VERSION 5.7 ;
  NOWIREEXTENSIONATPIN ON ;
  DIVIDERCHAR "/" ;
  BUSBITCHARS "[]" ;
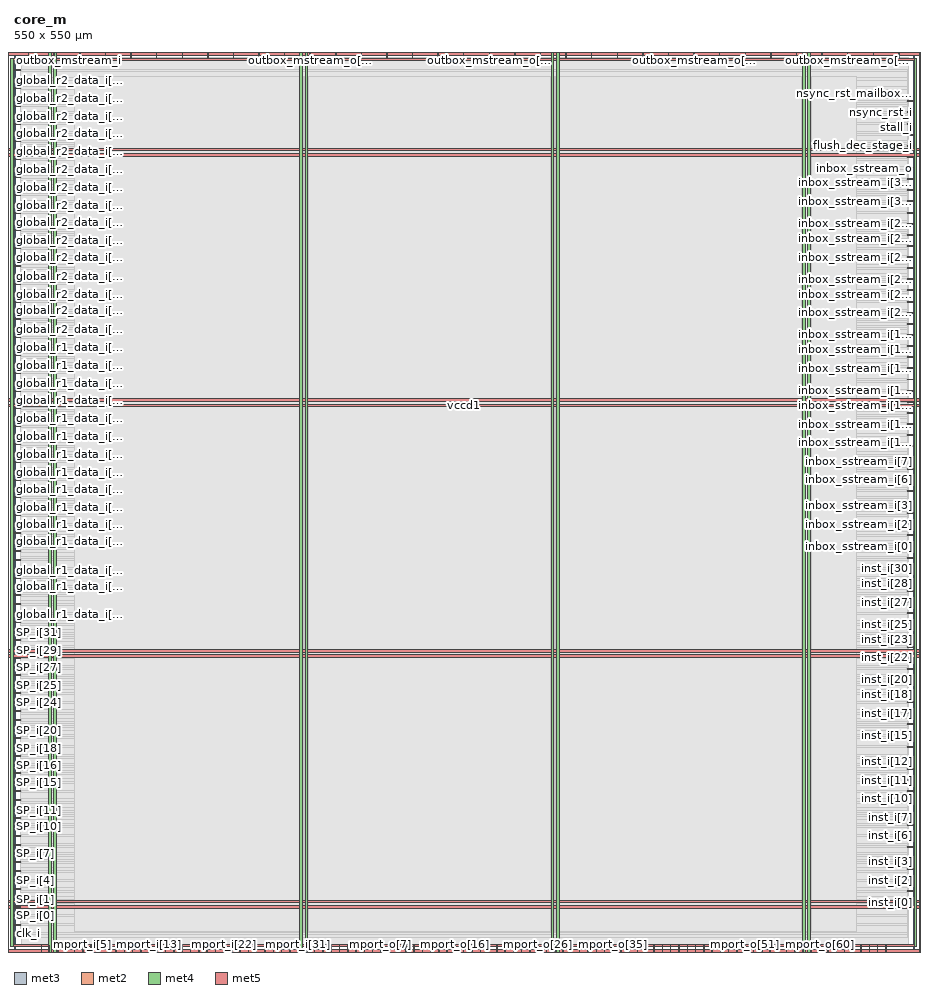
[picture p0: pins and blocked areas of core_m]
MACRO core_m
  CLASS BLOCK ;
  FOREIGN core_m ;
  ORIGIN 0.000 0.000 ;
  SIZE 550.000 BY 550.000 ;
  PIN SP_i[0]
    DIRECTION INPUT ;
    USE SIGNAL ;
    ANTENNAGATEAREA 0.159000 ;
    PORT
      LAYER met3 ;
        RECT 0.000 21.800 4.000 22.400 ;
    END
  END SP_i[0]
  PIN SP_i[10]
    DIRECTION INPUT ;
    USE SIGNAL ;
    ANTENNAGATEAREA 0.213000 ;
    PORT
      LAYER met3 ;
        RECT 0.000 76.200 4.000 76.800 ;
    END
  END SP_i[10]
  PIN SP_i[11]
    DIRECTION INPUT ;
    USE SIGNAL ;
    ANTENNAGATEAREA 0.213000 ;
    PORT
      LAYER met3 ;
        RECT 0.000 81.640 4.000 82.240 ;
    END
  END SP_i[11]
  PIN SP_i[12]
    DIRECTION INPUT ;
    USE SIGNAL ;
    ANTENNAGATEAREA 0.213000 ;
    PORT
      LAYER met3 ;
        RECT 0.000 87.080 4.000 87.680 ;
    END
  END SP_i[12]
  PIN SP_i[13]
    DIRECTION INPUT ;
    USE SIGNAL ;
    ANTENNAGATEAREA 0.213000 ;
    PORT
      LAYER met3 ;
        RECT 0.000 92.520 4.000 93.120 ;
    END
  END SP_i[13]
  PIN SP_i[14]
    DIRECTION INPUT ;
    USE SIGNAL ;
    ANTENNAGATEAREA 0.213000 ;
    PORT
      LAYER met3 ;
        RECT 0.000 97.960 4.000 98.560 ;
    END
  END SP_i[14]
  PIN SP_i[15]
    DIRECTION INPUT ;
    USE SIGNAL ;
    ANTENNAGATEAREA 0.213000 ;
    PORT
      LAYER met3 ;
        RECT 0.000 103.400 4.000 104.000 ;
    END
  END SP_i[15]
  PIN SP_i[16]
    DIRECTION INPUT ;
    USE SIGNAL ;
    ANTENNAGATEAREA 0.213000 ;
    PORT
      LAYER met3 ;
        RECT 0.000 108.840 4.000 109.440 ;
    END
  END SP_i[16]
  PIN SP_i[17]
    DIRECTION INPUT ;
    USE SIGNAL ;
    ANTENNAGATEAREA 0.213000 ;
    PORT
      LAYER met3 ;
        RECT 0.000 114.280 4.000 114.880 ;
    END
  END SP_i[17]
  PIN SP_i[18]
    DIRECTION INPUT ;
    USE SIGNAL ;
    ANTENNAGATEAREA 0.213000 ;
    PORT
      LAYER met3 ;
        RECT 0.000 119.720 4.000 120.320 ;
    END
  END SP_i[18]
  PIN SP_i[19]
    DIRECTION INPUT ;
    USE SIGNAL ;
    ANTENNAGATEAREA 0.213000 ;
    PORT
      LAYER met3 ;
        RECT 0.000 125.160 4.000 125.760 ;
    END
  END SP_i[19]
  PIN SP_i[1]
    DIRECTION INPUT ;
    USE SIGNAL ;
    ANTENNAGATEAREA 0.213000 ;
    PORT
      LAYER met3 ;
        RECT 0.000 27.240 4.000 27.840 ;
    END
  END SP_i[1]
  PIN SP_i[20]
    DIRECTION INPUT ;
    USE SIGNAL ;
    ANTENNAGATEAREA 0.213000 ;
    PORT
      LAYER met3 ;
        RECT 0.000 130.600 4.000 131.200 ;
    END
  END SP_i[20]
  PIN SP_i[21]
    DIRECTION INPUT ;
    USE SIGNAL ;
    ANTENNAGATEAREA 0.213000 ;
    PORT
      LAYER met3 ;
        RECT 0.000 136.040 4.000 136.640 ;
    END
  END SP_i[21]
  PIN SP_i[22]
    DIRECTION INPUT ;
    USE SIGNAL ;
    ANTENNAGATEAREA 0.213000 ;
    PORT
      LAYER met3 ;
        RECT 0.000 141.480 4.000 142.080 ;
    END
  END SP_i[22]
  PIN SP_i[23]
    DIRECTION INPUT ;
    USE SIGNAL ;
    ANTENNAGATEAREA 0.247500 ;
    PORT
      LAYER met3 ;
        RECT 0.000 146.920 4.000 147.520 ;
    END
  END SP_i[23]
  PIN SP_i[24]
    DIRECTION INPUT ;
    USE SIGNAL ;
    ANTENNAGATEAREA 0.159000 ;
    PORT
      LAYER met3 ;
        RECT 0.000 152.360 4.000 152.960 ;
    END
  END SP_i[24]
  PIN SP_i[25]
    DIRECTION INPUT ;
    USE SIGNAL ;
    ANTENNAGATEAREA 0.247500 ;
    PORT
      LAYER met3 ;
        RECT 0.000 157.800 4.000 158.400 ;
    END
  END SP_i[25]
  PIN SP_i[26]
    DIRECTION INPUT ;
    USE SIGNAL ;
    ANTENNAGATEAREA 0.213000 ;
    PORT
      LAYER met3 ;
        RECT 0.000 163.240 4.000 163.840 ;
    END
  END SP_i[26]
  PIN SP_i[27]
    DIRECTION INPUT ;
    USE SIGNAL ;
    ANTENNAGATEAREA 0.247500 ;
    PORT
      LAYER met3 ;
        RECT 0.000 168.680 4.000 169.280 ;
    END
  END SP_i[27]
  PIN SP_i[28]
    DIRECTION INPUT ;
    USE SIGNAL ;
    ANTENNAGATEAREA 0.247500 ;
    PORT
      LAYER met3 ;
        RECT 0.000 174.120 4.000 174.720 ;
    END
  END SP_i[28]
  PIN SP_i[29]
    DIRECTION INPUT ;
    USE SIGNAL ;
    ANTENNAGATEAREA 0.247500 ;
    PORT
      LAYER met3 ;
        RECT 0.000 179.560 4.000 180.160 ;
    END
  END SP_i[29]
  PIN SP_i[2]
    DIRECTION INPUT ;
    USE SIGNAL ;
    ANTENNAGATEAREA 0.213000 ;
    PORT
      LAYER met3 ;
        RECT 0.000 32.680 4.000 33.280 ;
    END
  END SP_i[2]
  PIN SP_i[30]
    DIRECTION INPUT ;
    USE SIGNAL ;
    ANTENNAGATEAREA 0.247500 ;
    PORT
      LAYER met3 ;
        RECT 0.000 185.000 4.000 185.600 ;
    END
  END SP_i[30]
  PIN SP_i[31]
    DIRECTION INPUT ;
    USE SIGNAL ;
    ANTENNAGATEAREA 0.213000 ;
    PORT
      LAYER met3 ;
        RECT 0.000 190.440 4.000 191.040 ;
    END
  END SP_i[31]
  PIN SP_i[3]
    DIRECTION INPUT ;
    USE SIGNAL ;
    ANTENNAGATEAREA 0.159000 ;
    PORT
      LAYER met3 ;
        RECT 0.000 38.120 4.000 38.720 ;
    END
  END SP_i[3]
  PIN SP_i[4]
    DIRECTION INPUT ;
    USE SIGNAL ;
    ANTENNAGATEAREA 0.213000 ;
    PORT
      LAYER met3 ;
        RECT 0.000 43.560 4.000 44.160 ;
    END
  END SP_i[4]
  PIN SP_i[5]
    DIRECTION INPUT ;
    USE SIGNAL ;
    ANTENNAGATEAREA 0.213000 ;
    PORT
      LAYER met3 ;
        RECT 0.000 49.000 4.000 49.600 ;
    END
  END SP_i[5]
  PIN SP_i[6]
    DIRECTION INPUT ;
    USE SIGNAL ;
    ANTENNAGATEAREA 0.213000 ;
    PORT
      LAYER met3 ;
        RECT 0.000 54.440 4.000 55.040 ;
    END
  END SP_i[6]
  PIN SP_i[7]
    DIRECTION INPUT ;
    USE SIGNAL ;
    ANTENNAGATEAREA 0.213000 ;
    PORT
      LAYER met3 ;
        RECT 0.000 59.880 4.000 60.480 ;
    END
  END SP_i[7]
  PIN SP_i[8]
    DIRECTION INPUT ;
    USE SIGNAL ;
    ANTENNAGATEAREA 0.213000 ;
    PORT
      LAYER met3 ;
        RECT 0.000 65.320 4.000 65.920 ;
    END
  END SP_i[8]
  PIN SP_i[9]
    DIRECTION INPUT ;
    USE SIGNAL ;
    ANTENNAGATEAREA 0.213000 ;
    PORT
      LAYER met3 ;
        RECT 0.000 70.760 4.000 71.360 ;
    END
  END SP_i[9]
  PIN clk_i
    DIRECTION INPUT ;
    USE SIGNAL ;
    ANTENNAGATEAREA 0.852000 ;
    PORT
      LAYER met3 ;
        RECT 0.000 10.920 4.000 11.520 ;
    END
  END clk_i
  PIN flush_dec_stage_i
    DIRECTION INPUT ;
    USE SIGNAL ;
    ANTENNAGATEAREA 0.247500 ;
    PORT
      LAYER met3 ;
        RECT 546.000 492.360 550.000 492.960 ;
    END
  END flush_dec_stage_i
  PIN global_r1_data_i[0]
    DIRECTION INPUT ;
    USE SIGNAL ;
    ANTENNAGATEAREA 0.196500 ;
    PORT
      LAYER met3 ;
        RECT 0.000 195.880 4.000 196.480 ;
    END
  END global_r1_data_i[0]
  PIN global_r1_data_i[10]
    DIRECTION INPUT ;
    USE SIGNAL ;
    ANTENNAGATEAREA 0.196500 ;
    PORT
      LAYER met3 ;
        RECT 0.000 250.280 4.000 250.880 ;
    END
  END global_r1_data_i[10]
  PIN global_r1_data_i[11]
    DIRECTION INPUT ;
    USE SIGNAL ;
    ANTENNAGATEAREA 0.196500 ;
    PORT
      LAYER met3 ;
        RECT 0.000 255.720 4.000 256.320 ;
    END
  END global_r1_data_i[11]
  PIN global_r1_data_i[12]
    DIRECTION INPUT ;
    USE SIGNAL ;
    ANTENNAGATEAREA 0.196500 ;
    PORT
      LAYER met3 ;
        RECT 0.000 261.160 4.000 261.760 ;
    END
  END global_r1_data_i[12]
  PIN global_r1_data_i[13]
    DIRECTION INPUT ;
    USE SIGNAL ;
    ANTENNAGATEAREA 0.196500 ;
    PORT
      LAYER met3 ;
        RECT 0.000 266.600 4.000 267.200 ;
    END
  END global_r1_data_i[13]
  PIN global_r1_data_i[14]
    DIRECTION INPUT ;
    USE SIGNAL ;
    ANTENNAGATEAREA 0.196500 ;
    PORT
      LAYER met3 ;
        RECT 0.000 272.040 4.000 272.640 ;
    END
  END global_r1_data_i[14]
  PIN global_r1_data_i[15]
    DIRECTION INPUT ;
    USE SIGNAL ;
    ANTENNAGATEAREA 0.196500 ;
    PORT
      LAYER met3 ;
        RECT 0.000 277.480 4.000 278.080 ;
    END
  END global_r1_data_i[15]
  PIN global_r1_data_i[16]
    DIRECTION INPUT ;
    USE SIGNAL ;
    ANTENNAGATEAREA 0.196500 ;
    PORT
      LAYER met3 ;
        RECT 0.000 282.920 4.000 283.520 ;
    END
  END global_r1_data_i[16]
  PIN global_r1_data_i[17]
    DIRECTION INPUT ;
    USE SIGNAL ;
    ANTENNAGATEAREA 0.196500 ;
    PORT
      LAYER met3 ;
        RECT 0.000 288.360 4.000 288.960 ;
    END
  END global_r1_data_i[17]
  PIN global_r1_data_i[18]
    DIRECTION INPUT ;
    USE SIGNAL ;
    ANTENNAGATEAREA 0.196500 ;
    PORT
      LAYER met3 ;
        RECT 0.000 293.800 4.000 294.400 ;
    END
  END global_r1_data_i[18]
  PIN global_r1_data_i[19]
    DIRECTION INPUT ;
    USE SIGNAL ;
    ANTENNAGATEAREA 0.196500 ;
    PORT
      LAYER met3 ;
        RECT 0.000 299.240 4.000 299.840 ;
    END
  END global_r1_data_i[19]
  PIN global_r1_data_i[1]
    DIRECTION INPUT ;
    USE SIGNAL ;
    ANTENNAGATEAREA 0.196500 ;
    PORT
      LAYER met3 ;
        RECT 0.000 201.320 4.000 201.920 ;
    END
  END global_r1_data_i[1]
  PIN global_r1_data_i[20]
    DIRECTION INPUT ;
    USE SIGNAL ;
    ANTENNAGATEAREA 0.196500 ;
    PORT
      LAYER met3 ;
        RECT 0.000 304.680 4.000 305.280 ;
    END
  END global_r1_data_i[20]
  PIN global_r1_data_i[21]
    DIRECTION INPUT ;
    USE SIGNAL ;
    ANTENNAGATEAREA 0.196500 ;
    PORT
      LAYER met3 ;
        RECT 0.000 310.120 4.000 310.720 ;
    END
  END global_r1_data_i[21]
  PIN global_r1_data_i[22]
    DIRECTION INPUT ;
    USE SIGNAL ;
    ANTENNAGATEAREA 0.196500 ;
    PORT
      LAYER met3 ;
        RECT 0.000 315.560 4.000 316.160 ;
    END
  END global_r1_data_i[22]
  PIN global_r1_data_i[23]
    DIRECTION INPUT ;
    USE SIGNAL ;
    ANTENNAGATEAREA 0.196500 ;
    PORT
      LAYER met3 ;
        RECT 0.000 321.000 4.000 321.600 ;
    END
  END global_r1_data_i[23]
  PIN global_r1_data_i[24]
    DIRECTION INPUT ;
    USE SIGNAL ;
    ANTENNAGATEAREA 0.196500 ;
    PORT
      LAYER met3 ;
        RECT 0.000 326.440 4.000 327.040 ;
    END
  END global_r1_data_i[24]
  PIN global_r1_data_i[25]
    DIRECTION INPUT ;
    USE SIGNAL ;
    ANTENNAGATEAREA 0.196500 ;
    PORT
      LAYER met3 ;
        RECT 0.000 331.880 4.000 332.480 ;
    END
  END global_r1_data_i[25]
  PIN global_r1_data_i[26]
    DIRECTION INPUT ;
    USE SIGNAL ;
    ANTENNAGATEAREA 0.196500 ;
    PORT
      LAYER met3 ;
        RECT 0.000 337.320 4.000 337.920 ;
    END
  END global_r1_data_i[26]
  PIN global_r1_data_i[27]
    DIRECTION INPUT ;
    USE SIGNAL ;
    ANTENNAGATEAREA 0.196500 ;
    PORT
      LAYER met3 ;
        RECT 0.000 342.760 4.000 343.360 ;
    END
  END global_r1_data_i[27]
  PIN global_r1_data_i[28]
    DIRECTION INPUT ;
    USE SIGNAL ;
    ANTENNAGATEAREA 0.196500 ;
    PORT
      LAYER met3 ;
        RECT 0.000 348.200 4.000 348.800 ;
    END
  END global_r1_data_i[28]
  PIN global_r1_data_i[29]
    DIRECTION INPUT ;
    USE SIGNAL ;
    ANTENNAGATEAREA 0.196500 ;
    PORT
      LAYER met3 ;
        RECT 0.000 353.640 4.000 354.240 ;
    END
  END global_r1_data_i[29]
  PIN global_r1_data_i[2]
    DIRECTION INPUT ;
    USE SIGNAL ;
    ANTENNAGATEAREA 0.196500 ;
    PORT
      LAYER met3 ;
        RECT 0.000 206.760 4.000 207.360 ;
    END
  END global_r1_data_i[2]
  PIN global_r1_data_i[30]
    DIRECTION INPUT ;
    USE SIGNAL ;
    ANTENNAGATEAREA 0.196500 ;
    PORT
      LAYER met3 ;
        RECT 0.000 359.080 4.000 359.680 ;
    END
  END global_r1_data_i[30]
  PIN global_r1_data_i[31]
    DIRECTION INPUT ;
    USE SIGNAL ;
    ANTENNAGATEAREA 0.196500 ;
    PORT
      LAYER met3 ;
        RECT 0.000 364.520 4.000 365.120 ;
    END
  END global_r1_data_i[31]
  PIN global_r1_data_i[3]
    DIRECTION INPUT ;
    USE SIGNAL ;
    ANTENNAGATEAREA 0.196500 ;
    PORT
      LAYER met3 ;
        RECT 0.000 212.200 4.000 212.800 ;
    END
  END global_r1_data_i[3]
  PIN global_r1_data_i[4]
    DIRECTION INPUT ;
    USE SIGNAL ;
    ANTENNAGATEAREA 0.196500 ;
    PORT
      LAYER met3 ;
        RECT 0.000 217.640 4.000 218.240 ;
    END
  END global_r1_data_i[4]
  PIN global_r1_data_i[5]
    DIRECTION INPUT ;
    USE SIGNAL ;
    ANTENNAGATEAREA 0.196500 ;
    PORT
      LAYER met3 ;
        RECT 0.000 223.080 4.000 223.680 ;
    END
  END global_r1_data_i[5]
  PIN global_r1_data_i[6]
    DIRECTION INPUT ;
    USE SIGNAL ;
    ANTENNAGATEAREA 0.196500 ;
    PORT
      LAYER met3 ;
        RECT 0.000 228.520 4.000 229.120 ;
    END
  END global_r1_data_i[6]
  PIN global_r1_data_i[7]
    DIRECTION INPUT ;
    USE SIGNAL ;
    ANTENNAGATEAREA 0.196500 ;
    PORT
      LAYER met3 ;
        RECT 0.000 233.960 4.000 234.560 ;
    END
  END global_r1_data_i[7]
  PIN global_r1_data_i[8]
    DIRECTION INPUT ;
    USE SIGNAL ;
    ANTENNAGATEAREA 0.196500 ;
    PORT
      LAYER met3 ;
        RECT 0.000 239.400 4.000 240.000 ;
    END
  END global_r1_data_i[8]
  PIN global_r1_data_i[9]
    DIRECTION INPUT ;
    USE SIGNAL ;
    ANTENNAGATEAREA 0.196500 ;
    PORT
      LAYER met3 ;
        RECT 0.000 244.840 4.000 245.440 ;
    END
  END global_r1_data_i[9]
  PIN global_r2_data_i[0]
    DIRECTION INPUT ;
    USE SIGNAL ;
    ANTENNAGATEAREA 0.196500 ;
    PORT
      LAYER met3 ;
        RECT 0.000 369.960 4.000 370.560 ;
    END
  END global_r2_data_i[0]
  PIN global_r2_data_i[10]
    DIRECTION INPUT ;
    USE SIGNAL ;
    ANTENNAGATEAREA 0.196500 ;
    PORT
      LAYER met3 ;
        RECT 0.000 424.360 4.000 424.960 ;
    END
  END global_r2_data_i[10]
  PIN global_r2_data_i[11]
    DIRECTION INPUT ;
    USE SIGNAL ;
    ANTENNAGATEAREA 0.196500 ;
    PORT
      LAYER met3 ;
        RECT 0.000 429.800 4.000 430.400 ;
    END
  END global_r2_data_i[11]
  PIN global_r2_data_i[12]
    DIRECTION INPUT ;
    USE SIGNAL ;
    ANTENNAGATEAREA 0.196500 ;
    PORT
      LAYER met3 ;
        RECT 0.000 435.240 4.000 435.840 ;
    END
  END global_r2_data_i[12]
  PIN global_r2_data_i[13]
    DIRECTION INPUT ;
    USE SIGNAL ;
    ANTENNAGATEAREA 0.196500 ;
    PORT
      LAYER met3 ;
        RECT 0.000 440.680 4.000 441.280 ;
    END
  END global_r2_data_i[13]
  PIN global_r2_data_i[14]
    DIRECTION INPUT ;
    USE SIGNAL ;
    ANTENNAGATEAREA 0.196500 ;
    PORT
      LAYER met3 ;
        RECT 0.000 446.120 4.000 446.720 ;
    END
  END global_r2_data_i[14]
  PIN global_r2_data_i[15]
    DIRECTION INPUT ;
    USE SIGNAL ;
    ANTENNAGATEAREA 0.196500 ;
    PORT
      LAYER met3 ;
        RECT 0.000 451.560 4.000 452.160 ;
    END
  END global_r2_data_i[15]
  PIN global_r2_data_i[16]
    DIRECTION INPUT ;
    USE SIGNAL ;
    ANTENNAGATEAREA 0.196500 ;
    PORT
      LAYER met3 ;
        RECT 0.000 457.000 4.000 457.600 ;
    END
  END global_r2_data_i[16]
  PIN global_r2_data_i[17]
    DIRECTION INPUT ;
    USE SIGNAL ;
    ANTENNAGATEAREA 0.196500 ;
    PORT
      LAYER met3 ;
        RECT 0.000 462.440 4.000 463.040 ;
    END
  END global_r2_data_i[17]
  PIN global_r2_data_i[18]
    DIRECTION INPUT ;
    USE SIGNAL ;
    ANTENNAGATEAREA 0.196500 ;
    PORT
      LAYER met3 ;
        RECT 0.000 467.880 4.000 468.480 ;
    END
  END global_r2_data_i[18]
  PIN global_r2_data_i[19]
    DIRECTION INPUT ;
    USE SIGNAL ;
    ANTENNAGATEAREA 0.196500 ;
    PORT
      LAYER met3 ;
        RECT 0.000 473.320 4.000 473.920 ;
    END
  END global_r2_data_i[19]
  PIN global_r2_data_i[1]
    DIRECTION INPUT ;
    USE SIGNAL ;
    ANTENNAGATEAREA 0.196500 ;
    PORT
      LAYER met3 ;
        RECT 0.000 375.400 4.000 376.000 ;
    END
  END global_r2_data_i[1]
  PIN global_r2_data_i[20]
    DIRECTION INPUT ;
    USE SIGNAL ;
    ANTENNAGATEAREA 0.196500 ;
    PORT
      LAYER met3 ;
        RECT 0.000 478.760 4.000 479.360 ;
    END
  END global_r2_data_i[20]
  PIN global_r2_data_i[21]
    DIRECTION INPUT ;
    USE SIGNAL ;
    ANTENNAGATEAREA 0.196500 ;
    PORT
      LAYER met3 ;
        RECT 0.000 484.200 4.000 484.800 ;
    END
  END global_r2_data_i[21]
  PIN global_r2_data_i[22]
    DIRECTION INPUT ;
    USE SIGNAL ;
    ANTENNAGATEAREA 0.196500 ;
    PORT
      LAYER met3 ;
        RECT 0.000 489.640 4.000 490.240 ;
    END
  END global_r2_data_i[22]
  PIN global_r2_data_i[23]
    DIRECTION INPUT ;
    USE SIGNAL ;
    ANTENNAGATEAREA 0.196500 ;
    PORT
      LAYER met3 ;
        RECT 0.000 495.080 4.000 495.680 ;
    END
  END global_r2_data_i[23]
  PIN global_r2_data_i[24]
    DIRECTION INPUT ;
    USE SIGNAL ;
    ANTENNAGATEAREA 0.196500 ;
    PORT
      LAYER met3 ;
        RECT 0.000 500.520 4.000 501.120 ;
    END
  END global_r2_data_i[24]
  PIN global_r2_data_i[25]
    DIRECTION INPUT ;
    USE SIGNAL ;
    ANTENNAGATEAREA 0.196500 ;
    PORT
      LAYER met3 ;
        RECT 0.000 505.960 4.000 506.560 ;
    END
  END global_r2_data_i[25]
  PIN global_r2_data_i[26]
    DIRECTION INPUT ;
    USE SIGNAL ;
    ANTENNAGATEAREA 0.196500 ;
    PORT
      LAYER met3 ;
        RECT 0.000 511.400 4.000 512.000 ;
    END
  END global_r2_data_i[26]
  PIN global_r2_data_i[27]
    DIRECTION INPUT ;
    USE SIGNAL ;
    ANTENNAGATEAREA 0.196500 ;
    PORT
      LAYER met3 ;
        RECT 0.000 516.840 4.000 517.440 ;
    END
  END global_r2_data_i[27]
  PIN global_r2_data_i[28]
    DIRECTION INPUT ;
    USE SIGNAL ;
    ANTENNAGATEAREA 0.196500 ;
    PORT
      LAYER met3 ;
        RECT 0.000 522.280 4.000 522.880 ;
    END
  END global_r2_data_i[28]
  PIN global_r2_data_i[29]
    DIRECTION INPUT ;
    USE SIGNAL ;
    ANTENNAGATEAREA 0.196500 ;
    PORT
      LAYER met3 ;
        RECT 0.000 527.720 4.000 528.320 ;
    END
  END global_r2_data_i[29]
  PIN global_r2_data_i[2]
    DIRECTION INPUT ;
    USE SIGNAL ;
    ANTENNAGATEAREA 0.196500 ;
    PORT
      LAYER met3 ;
        RECT 0.000 380.840 4.000 381.440 ;
    END
  END global_r2_data_i[2]
  PIN global_r2_data_i[30]
    DIRECTION INPUT ;
    USE SIGNAL ;
    ANTENNAGATEAREA 0.196500 ;
    PORT
      LAYER met3 ;
        RECT 0.000 533.160 4.000 533.760 ;
    END
  END global_r2_data_i[30]
  PIN global_r2_data_i[31]
    DIRECTION INPUT ;
    USE SIGNAL ;
    ANTENNAGATEAREA 0.196500 ;
    PORT
      LAYER met3 ;
        RECT 0.000 538.600 4.000 539.200 ;
    END
  END global_r2_data_i[31]
  PIN global_r2_data_i[3]
    DIRECTION INPUT ;
    USE SIGNAL ;
    ANTENNAGATEAREA 0.196500 ;
    PORT
      LAYER met3 ;
        RECT 0.000 386.280 4.000 386.880 ;
    END
  END global_r2_data_i[3]
  PIN global_r2_data_i[4]
    DIRECTION INPUT ;
    USE SIGNAL ;
    ANTENNAGATEAREA 0.196500 ;
    PORT
      LAYER met3 ;
        RECT 0.000 391.720 4.000 392.320 ;
    END
  END global_r2_data_i[4]
  PIN global_r2_data_i[5]
    DIRECTION INPUT ;
    USE SIGNAL ;
    ANTENNAGATEAREA 0.196500 ;
    PORT
      LAYER met3 ;
        RECT 0.000 397.160 4.000 397.760 ;
    END
  END global_r2_data_i[5]
  PIN global_r2_data_i[6]
    DIRECTION INPUT ;
    USE SIGNAL ;
    ANTENNAGATEAREA 0.196500 ;
    PORT
      LAYER met3 ;
        RECT 0.000 402.600 4.000 403.200 ;
    END
  END global_r2_data_i[6]
  PIN global_r2_data_i[7]
    DIRECTION INPUT ;
    USE SIGNAL ;
    ANTENNAGATEAREA 0.196500 ;
    PORT
      LAYER met3 ;
        RECT 0.000 408.040 4.000 408.640 ;
    END
  END global_r2_data_i[7]
  PIN global_r2_data_i[8]
    DIRECTION INPUT ;
    USE SIGNAL ;
    ANTENNAGATEAREA 0.196500 ;
    PORT
      LAYER met3 ;
        RECT 0.000 413.480 4.000 414.080 ;
    END
  END global_r2_data_i[8]
  PIN global_r2_data_i[9]
    DIRECTION INPUT ;
    USE SIGNAL ;
    ANTENNAGATEAREA 0.196500 ;
    PORT
      LAYER met3 ;
        RECT 0.000 418.920 4.000 419.520 ;
    END
  END global_r2_data_i[9]
  PIN inbox_sstream_i[0]
    DIRECTION INPUT ;
    USE SIGNAL ;
    ANTENNAGATEAREA 0.159000 ;
    PORT
      LAYER met3 ;
        RECT 546.000 247.560 550.000 248.160 ;
    END
  END inbox_sstream_i[0]
  PIN inbox_sstream_i[10]
    DIRECTION INPUT ;
    USE SIGNAL ;
    ANTENNAGATEAREA 0.159000 ;
    PORT
      LAYER met3 ;
        RECT 546.000 315.560 550.000 316.160 ;
    END
  END inbox_sstream_i[10]
  PIN inbox_sstream_i[11]
    DIRECTION INPUT ;
    USE SIGNAL ;
    ANTENNAGATEAREA 0.213000 ;
    PORT
      LAYER met3 ;
        RECT 546.000 322.360 550.000 322.960 ;
    END
  END inbox_sstream_i[11]
  PIN inbox_sstream_i[12]
    DIRECTION INPUT ;
    USE SIGNAL ;
    ANTENNAGATEAREA 0.213000 ;
    PORT
      LAYER met3 ;
        RECT 546.000 329.160 550.000 329.760 ;
    END
  END inbox_sstream_i[12]
  PIN inbox_sstream_i[13]
    DIRECTION INPUT ;
    USE SIGNAL ;
    ANTENNAGATEAREA 0.213000 ;
    PORT
      LAYER met3 ;
        RECT 546.000 335.960 550.000 336.560 ;
    END
  END inbox_sstream_i[13]
  PIN inbox_sstream_i[14]
    DIRECTION INPUT ;
    USE SIGNAL ;
    ANTENNAGATEAREA 0.159000 ;
    PORT
      LAYER met3 ;
        RECT 546.000 342.760 550.000 343.360 ;
    END
  END inbox_sstream_i[14]
  PIN inbox_sstream_i[15]
    DIRECTION INPUT ;
    USE SIGNAL ;
    ANTENNAGATEAREA 0.213000 ;
    PORT
      LAYER met3 ;
        RECT 546.000 349.560 550.000 350.160 ;
    END
  END inbox_sstream_i[15]
  PIN inbox_sstream_i[16]
    DIRECTION INPUT ;
    USE SIGNAL ;
    ANTENNAGATEAREA 0.196500 ;
    PORT
      LAYER met3 ;
        RECT 546.000 356.360 550.000 356.960 ;
    END
  END inbox_sstream_i[16]
  PIN inbox_sstream_i[17]
    DIRECTION INPUT ;
    USE SIGNAL ;
    ANTENNAGATEAREA 0.213000 ;
    PORT
      LAYER met3 ;
        RECT 546.000 363.160 550.000 363.760 ;
    END
  END inbox_sstream_i[17]
  PIN inbox_sstream_i[18]
    DIRECTION INPUT ;
    USE SIGNAL ;
    ANTENNAGATEAREA 0.213000 ;
    PORT
      LAYER met3 ;
        RECT 546.000 369.960 550.000 370.560 ;
    END
  END inbox_sstream_i[18]
  PIN inbox_sstream_i[19]
    DIRECTION INPUT ;
    USE SIGNAL ;
    ANTENNAGATEAREA 0.213000 ;
    PORT
      LAYER met3 ;
        RECT 546.000 376.760 550.000 377.360 ;
    END
  END inbox_sstream_i[19]
  PIN inbox_sstream_i[1]
    DIRECTION INPUT ;
    USE SIGNAL ;
    ANTENNAGATEAREA 0.213000 ;
    PORT
      LAYER met3 ;
        RECT 546.000 254.360 550.000 254.960 ;
    END
  END inbox_sstream_i[1]
  PIN inbox_sstream_i[20]
    DIRECTION INPUT ;
    USE SIGNAL ;
    ANTENNAGATEAREA 0.196500 ;
    PORT
      LAYER met3 ;
        RECT 546.000 383.560 550.000 384.160 ;
    END
  END inbox_sstream_i[20]
  PIN inbox_sstream_i[21]
    DIRECTION INPUT ;
    USE SIGNAL ;
    ANTENNAGATEAREA 0.196500 ;
    PORT
      LAYER met3 ;
        RECT 546.000 390.360 550.000 390.960 ;
    END
  END inbox_sstream_i[21]
  PIN inbox_sstream_i[22]
    DIRECTION INPUT ;
    USE SIGNAL ;
    ANTENNAGATEAREA 0.126000 ;
    PORT
      LAYER met3 ;
        RECT 546.000 397.160 550.000 397.760 ;
    END
  END inbox_sstream_i[22]
  PIN inbox_sstream_i[23]
    DIRECTION INPUT ;
    USE SIGNAL ;
    ANTENNAGATEAREA 0.196500 ;
    PORT
      LAYER met3 ;
        RECT 546.000 403.960 550.000 404.560 ;
    END
  END inbox_sstream_i[23]
  PIN inbox_sstream_i[24]
    DIRECTION INPUT ;
    USE SIGNAL ;
    ANTENNAGATEAREA 0.213000 ;
    PORT
      LAYER met3 ;
        RECT 546.000 410.760 550.000 411.360 ;
    END
  END inbox_sstream_i[24]
  PIN inbox_sstream_i[25]
    DIRECTION INPUT ;
    USE SIGNAL ;
    ANTENNAGATEAREA 0.196500 ;
    PORT
      LAYER met3 ;
        RECT 546.000 417.560 550.000 418.160 ;
    END
  END inbox_sstream_i[25]
  PIN inbox_sstream_i[26]
    DIRECTION INPUT ;
    USE SIGNAL ;
    ANTENNAGATEAREA 0.196500 ;
    PORT
      LAYER met3 ;
        RECT 546.000 424.360 550.000 424.960 ;
    END
  END inbox_sstream_i[26]
  PIN inbox_sstream_i[27]
    DIRECTION INPUT ;
    USE SIGNAL ;
    ANTENNAGATEAREA 0.196500 ;
    PORT
      LAYER met3 ;
        RECT 546.000 431.160 550.000 431.760 ;
    END
  END inbox_sstream_i[27]
  PIN inbox_sstream_i[28]
    DIRECTION INPUT ;
    USE SIGNAL ;
    ANTENNAGATEAREA 0.196500 ;
    PORT
      LAYER met3 ;
        RECT 546.000 437.960 550.000 438.560 ;
    END
  END inbox_sstream_i[28]
  PIN inbox_sstream_i[29]
    DIRECTION INPUT ;
    USE SIGNAL ;
    ANTENNAGATEAREA 0.196500 ;
    PORT
      LAYER met3 ;
        RECT 546.000 444.760 550.000 445.360 ;
    END
  END inbox_sstream_i[29]
  PIN inbox_sstream_i[2]
    DIRECTION INPUT ;
    USE SIGNAL ;
    ANTENNAGATEAREA 0.213000 ;
    PORT
      LAYER met3 ;
        RECT 546.000 261.160 550.000 261.760 ;
    END
  END inbox_sstream_i[2]
  PIN inbox_sstream_i[30]
    DIRECTION INPUT ;
    USE SIGNAL ;
    ANTENNAGATEAREA 0.196500 ;
    PORT
      LAYER met3 ;
        RECT 546.000 451.560 550.000 452.160 ;
    END
  END inbox_sstream_i[30]
  PIN inbox_sstream_i[31]
    DIRECTION INPUT ;
    USE SIGNAL ;
    ANTENNAGATEAREA 0.196500 ;
    PORT
      LAYER met3 ;
        RECT 546.000 458.360 550.000 458.960 ;
    END
  END inbox_sstream_i[31]
  PIN inbox_sstream_i[32]
    DIRECTION INPUT ;
    USE SIGNAL ;
    ANTENNAGATEAREA 0.159000 ;
    PORT
      LAYER met3 ;
        RECT 546.000 465.160 550.000 465.760 ;
    END
  END inbox_sstream_i[32]
  PIN inbox_sstream_i[33]
    DIRECTION INPUT ;
    USE SIGNAL ;
    PORT
      LAYER met3 ;
        RECT 546.000 471.960 550.000 472.560 ;
    END
  END inbox_sstream_i[33]
  PIN inbox_sstream_i[3]
    DIRECTION INPUT ;
    USE SIGNAL ;
    ANTENNAGATEAREA 0.159000 ;
    PORT
      LAYER met3 ;
        RECT 546.000 267.960 550.000 268.560 ;
    END
  END inbox_sstream_i[3]
  PIN inbox_sstream_i[4]
    DIRECTION INPUT ;
    USE SIGNAL ;
    ANTENNAGATEAREA 0.213000 ;
    PORT
      LAYER met3 ;
        RECT 546.000 274.760 550.000 275.360 ;
    END
  END inbox_sstream_i[4]
  PIN inbox_sstream_i[5]
    DIRECTION INPUT ;
    USE SIGNAL ;
    ANTENNAGATEAREA 0.213000 ;
    PORT
      LAYER met3 ;
        RECT 546.000 281.560 550.000 282.160 ;
    END
  END inbox_sstream_i[5]
  PIN inbox_sstream_i[6]
    DIRECTION INPUT ;
    USE SIGNAL ;
    ANTENNAGATEAREA 0.213000 ;
    PORT
      LAYER met3 ;
        RECT 546.000 288.360 550.000 288.960 ;
    END
  END inbox_sstream_i[6]
  PIN inbox_sstream_i[7]
    DIRECTION INPUT ;
    USE SIGNAL ;
    ANTENNAGATEAREA 0.213000 ;
    PORT
      LAYER met3 ;
        RECT 546.000 295.160 550.000 295.760 ;
    END
  END inbox_sstream_i[7]
  PIN inbox_sstream_i[8]
    DIRECTION INPUT ;
    USE SIGNAL ;
    ANTENNAGATEAREA 0.213000 ;
    PORT
      LAYER met3 ;
        RECT 546.000 301.960 550.000 302.560 ;
    END
  END inbox_sstream_i[8]
  PIN inbox_sstream_i[9]
    DIRECTION INPUT ;
    USE SIGNAL ;
    ANTENNAGATEAREA 0.126000 ;
    PORT
      LAYER met3 ;
        RECT 546.000 308.760 550.000 309.360 ;
    END
  END inbox_sstream_i[9]
  PIN inbox_sstream_o
    DIRECTION OUTPUT TRISTATE ;
    USE SIGNAL ;
    ANTENNADIFFAREA 0.445500 ;
    PORT
      LAYER met3 ;
        RECT 546.000 478.760 550.000 479.360 ;
    END
  END inbox_sstream_o
  PIN inst_i[0]
    DIRECTION INPUT ;
    USE SIGNAL ;
    ANTENNAGATEAREA 0.196500 ;
    PORT
      LAYER met3 ;
        RECT 546.000 29.960 550.000 30.560 ;
    END
  END inst_i[0]
  PIN inst_i[10]
    DIRECTION INPUT ;
    USE SIGNAL ;
    ANTENNAGATEAREA 0.196500 ;
    PORT
      LAYER met3 ;
        RECT 546.000 97.960 550.000 98.560 ;
    END
  END inst_i[10]
  PIN inst_i[11]
    DIRECTION INPUT ;
    USE SIGNAL ;
    ANTENNAGATEAREA 0.196500 ;
    PORT
      LAYER met3 ;
        RECT 546.000 104.760 550.000 105.360 ;
    END
  END inst_i[11]
  PIN inst_i[12]
    DIRECTION INPUT ;
    USE SIGNAL ;
    ANTENNAGATEAREA 0.196500 ;
    PORT
      LAYER met3 ;
        RECT 546.000 111.560 550.000 112.160 ;
    END
  END inst_i[12]
  PIN inst_i[13]
    DIRECTION INPUT ;
    USE SIGNAL ;
    ANTENNAGATEAREA 0.196500 ;
    PORT
      LAYER met3 ;
        RECT 546.000 118.360 550.000 118.960 ;
    END
  END inst_i[13]
  PIN inst_i[14]
    DIRECTION INPUT ;
    USE SIGNAL ;
    ANTENNAGATEAREA 0.196500 ;
    PORT
      LAYER met3 ;
        RECT 546.000 125.160 550.000 125.760 ;
    END
  END inst_i[14]
  PIN inst_i[15]
    DIRECTION INPUT ;
    USE SIGNAL ;
    ANTENNAGATEAREA 0.196500 ;
    PORT
      LAYER met3 ;
        RECT 546.000 131.960 550.000 132.560 ;
    END
  END inst_i[15]
  PIN inst_i[16]
    DIRECTION INPUT ;
    USE SIGNAL ;
    ANTENNAGATEAREA 0.196500 ;
    PORT
      LAYER met3 ;
        RECT 546.000 138.760 550.000 139.360 ;
    END
  END inst_i[16]
  PIN inst_i[17]
    DIRECTION INPUT ;
    USE SIGNAL ;
    ANTENNAGATEAREA 0.196500 ;
    PORT
      LAYER met3 ;
        RECT 546.000 145.560 550.000 146.160 ;
    END
  END inst_i[17]
  PIN inst_i[18]
    DIRECTION INPUT ;
    USE SIGNAL ;
    ANTENNAGATEAREA 0.196500 ;
    PORT
      LAYER met3 ;
        RECT 546.000 152.360 550.000 152.960 ;
    END
  END inst_i[18]
  PIN inst_i[19]
    DIRECTION INPUT ;
    USE SIGNAL ;
    ANTENNAGATEAREA 0.196500 ;
    PORT
      LAYER met3 ;
        RECT 546.000 159.160 550.000 159.760 ;
    END
  END inst_i[19]
  PIN inst_i[1]
    DIRECTION INPUT ;
    USE SIGNAL ;
    ANTENNAGATEAREA 0.196500 ;
    PORT
      LAYER met3 ;
        RECT 546.000 36.760 550.000 37.360 ;
    END
  END inst_i[1]
  PIN inst_i[20]
    DIRECTION INPUT ;
    USE SIGNAL ;
    ANTENNAGATEAREA 0.196500 ;
    PORT
      LAYER met3 ;
        RECT 546.000 165.960 550.000 166.560 ;
    END
  END inst_i[20]
  PIN inst_i[21]
    DIRECTION INPUT ;
    USE SIGNAL ;
    ANTENNAGATEAREA 0.196500 ;
    PORT
      LAYER met3 ;
        RECT 546.000 172.760 550.000 173.360 ;
    END
  END inst_i[21]
  PIN inst_i[22]
    DIRECTION INPUT ;
    USE SIGNAL ;
    ANTENNAGATEAREA 0.196500 ;
    PORT
      LAYER met3 ;
        RECT 546.000 179.560 550.000 180.160 ;
    END
  END inst_i[22]
  PIN inst_i[23]
    DIRECTION INPUT ;
    USE SIGNAL ;
    ANTENNAGATEAREA 0.196500 ;
    PORT
      LAYER met3 ;
        RECT 546.000 186.360 550.000 186.960 ;
    END
  END inst_i[23]
  PIN inst_i[24]
    DIRECTION INPUT ;
    USE SIGNAL ;
    ANTENNAGATEAREA 0.196500 ;
    PORT
      LAYER met3 ;
        RECT 546.000 193.160 550.000 193.760 ;
    END
  END inst_i[24]
  PIN inst_i[25]
    DIRECTION INPUT ;
    USE SIGNAL ;
    ANTENNAGATEAREA 0.196500 ;
    PORT
      LAYER met3 ;
        RECT 546.000 199.960 550.000 200.560 ;
    END
  END inst_i[25]
  PIN inst_i[26]
    DIRECTION INPUT ;
    USE SIGNAL ;
    ANTENNAGATEAREA 0.196500 ;
    PORT
      LAYER met3 ;
        RECT 546.000 206.760 550.000 207.360 ;
    END
  END inst_i[26]
  PIN inst_i[27]
    DIRECTION INPUT ;
    USE SIGNAL ;
    ANTENNAGATEAREA 0.196500 ;
    PORT
      LAYER met3 ;
        RECT 546.000 213.560 550.000 214.160 ;
    END
  END inst_i[27]
  PIN inst_i[28]
    DIRECTION INPUT ;
    USE SIGNAL ;
    ANTENNAGATEAREA 0.196500 ;
    PORT
      LAYER met3 ;
        RECT 546.000 220.360 550.000 220.960 ;
    END
  END inst_i[28]
  PIN inst_i[29]
    DIRECTION INPUT ;
    USE SIGNAL ;
    ANTENNAGATEAREA 0.196500 ;
    PORT
      LAYER met3 ;
        RECT 546.000 227.160 550.000 227.760 ;
    END
  END inst_i[29]
  PIN inst_i[2]
    DIRECTION INPUT ;
    USE SIGNAL ;
    ANTENNAGATEAREA 0.196500 ;
    PORT
      LAYER met3 ;
        RECT 546.000 43.560 550.000 44.160 ;
    END
  END inst_i[2]
  PIN inst_i[30]
    DIRECTION INPUT ;
    USE SIGNAL ;
    ANTENNAGATEAREA 0.196500 ;
    PORT
      LAYER met3 ;
        RECT 546.000 233.960 550.000 234.560 ;
    END
  END inst_i[30]
  PIN inst_i[31]
    DIRECTION INPUT ;
    USE SIGNAL ;
    ANTENNAGATEAREA 0.196500 ;
    PORT
      LAYER met3 ;
        RECT 546.000 240.760 550.000 241.360 ;
    END
  END inst_i[31]
  PIN inst_i[3]
    DIRECTION INPUT ;
    USE SIGNAL ;
    ANTENNAGATEAREA 0.196500 ;
    PORT
      LAYER met3 ;
        RECT 546.000 50.360 550.000 50.960 ;
    END
  END inst_i[3]
  PIN inst_i[4]
    DIRECTION INPUT ;
    USE SIGNAL ;
    ANTENNAGATEAREA 0.196500 ;
    PORT
      LAYER met3 ;
        RECT 546.000 57.160 550.000 57.760 ;
    END
  END inst_i[4]
  PIN inst_i[5]
    DIRECTION INPUT ;
    USE SIGNAL ;
    ANTENNAGATEAREA 0.196500 ;
    PORT
      LAYER met3 ;
        RECT 546.000 63.960 550.000 64.560 ;
    END
  END inst_i[5]
  PIN inst_i[6]
    DIRECTION INPUT ;
    USE SIGNAL ;
    ANTENNAGATEAREA 0.196500 ;
    PORT
      LAYER met3 ;
        RECT 546.000 70.760 550.000 71.360 ;
    END
  END inst_i[6]
  PIN inst_i[7]
    DIRECTION INPUT ;
    USE SIGNAL ;
    ANTENNAGATEAREA 0.196500 ;
    PORT
      LAYER met3 ;
        RECT 546.000 77.560 550.000 78.160 ;
    END
  END inst_i[7]
  PIN inst_i[8]
    DIRECTION INPUT ;
    USE SIGNAL ;
    ANTENNAGATEAREA 0.196500 ;
    PORT
      LAYER met3 ;
        RECT 546.000 84.360 550.000 84.960 ;
    END
  END inst_i[8]
  PIN inst_i[9]
    DIRECTION INPUT ;
    USE SIGNAL ;
    ANTENNAGATEAREA 0.196500 ;
    PORT
      LAYER met3 ;
        RECT 546.000 91.160 550.000 91.760 ;
    END
  END inst_i[9]
  PIN jump_request_o
    DIRECTION OUTPUT TRISTATE ;
    USE SIGNAL ;
    ANTENNADIFFAREA 0.445500 ;
    PORT
      LAYER met3 ;
        RECT 546.000 485.560 550.000 486.160 ;
    END
  END jump_request_o
  PIN mport_i[0]
    DIRECTION INPUT ;
    USE SIGNAL ;
    ANTENNAGATEAREA 0.196500 ;
    PORT
      LAYER met2 ;
        RECT 16.650 0.000 16.930 4.000 ;
    END
  END mport_i[0]
  PIN mport_i[10]
    DIRECTION INPUT ;
    USE SIGNAL ;
    ANTENNAGATEAREA 0.196500 ;
    PORT
      LAYER met2 ;
        RECT 67.250 0.000 67.530 4.000 ;
    END
  END mport_i[10]
  PIN mport_i[11]
    DIRECTION INPUT ;
    USE SIGNAL ;
    ANTENNAGATEAREA 0.196500 ;
    PORT
      LAYER met2 ;
        RECT 72.310 0.000 72.590 4.000 ;
    END
  END mport_i[11]
  PIN mport_i[12]
    DIRECTION INPUT ;
    USE SIGNAL ;
    ANTENNAGATEAREA 0.196500 ;
    PORT
      LAYER met2 ;
        RECT 77.370 0.000 77.650 4.000 ;
    END
  END mport_i[12]
  PIN mport_i[13]
    DIRECTION INPUT ;
    USE SIGNAL ;
    ANTENNAGATEAREA 0.196500 ;
    PORT
      LAYER met2 ;
        RECT 82.430 0.000 82.710 4.000 ;
    END
  END mport_i[13]
  PIN mport_i[14]
    DIRECTION INPUT ;
    USE SIGNAL ;
    ANTENNAGATEAREA 0.196500 ;
    PORT
      LAYER met2 ;
        RECT 87.490 0.000 87.770 4.000 ;
    END
  END mport_i[14]
  PIN mport_i[15]
    DIRECTION INPUT ;
    USE SIGNAL ;
    ANTENNAGATEAREA 0.196500 ;
    PORT
      LAYER met2 ;
        RECT 92.550 0.000 92.830 4.000 ;
    END
  END mport_i[15]
  PIN mport_i[16]
    DIRECTION INPUT ;
    USE SIGNAL ;
    ANTENNAGATEAREA 0.196500 ;
    PORT
      LAYER met2 ;
        RECT 97.610 0.000 97.890 4.000 ;
    END
  END mport_i[16]
  PIN mport_i[17]
    DIRECTION INPUT ;
    USE SIGNAL ;
    ANTENNAGATEAREA 0.196500 ;
    PORT
      LAYER met2 ;
        RECT 102.670 0.000 102.950 4.000 ;
    END
  END mport_i[17]
  PIN mport_i[18]
    DIRECTION INPUT ;
    USE SIGNAL ;
    ANTENNAGATEAREA 0.196500 ;
    PORT
      LAYER met2 ;
        RECT 107.730 0.000 108.010 4.000 ;
    END
  END mport_i[18]
  PIN mport_i[19]
    DIRECTION INPUT ;
    USE SIGNAL ;
    ANTENNAGATEAREA 0.196500 ;
    PORT
      LAYER met2 ;
        RECT 112.790 0.000 113.070 4.000 ;
    END
  END mport_i[19]
  PIN mport_i[1]
    DIRECTION INPUT ;
    USE SIGNAL ;
    ANTENNAGATEAREA 0.196500 ;
    PORT
      LAYER met2 ;
        RECT 21.710 0.000 21.990 4.000 ;
    END
  END mport_i[1]
  PIN mport_i[20]
    DIRECTION INPUT ;
    USE SIGNAL ;
    ANTENNAGATEAREA 0.196500 ;
    PORT
      LAYER met2 ;
        RECT 117.850 0.000 118.130 4.000 ;
    END
  END mport_i[20]
  PIN mport_i[21]
    DIRECTION INPUT ;
    USE SIGNAL ;
    ANTENNAGATEAREA 0.196500 ;
    PORT
      LAYER met2 ;
        RECT 122.910 0.000 123.190 4.000 ;
    END
  END mport_i[21]
  PIN mport_i[22]
    DIRECTION INPUT ;
    USE SIGNAL ;
    ANTENNAGATEAREA 0.196500 ;
    PORT
      LAYER met2 ;
        RECT 127.970 0.000 128.250 4.000 ;
    END
  END mport_i[22]
  PIN mport_i[23]
    DIRECTION INPUT ;
    USE SIGNAL ;
    ANTENNAGATEAREA 0.196500 ;
    PORT
      LAYER met2 ;
        RECT 133.030 0.000 133.310 4.000 ;
    END
  END mport_i[23]
  PIN mport_i[24]
    DIRECTION INPUT ;
    USE SIGNAL ;
    ANTENNAGATEAREA 0.196500 ;
    PORT
      LAYER met2 ;
        RECT 138.090 0.000 138.370 4.000 ;
    END
  END mport_i[24]
  PIN mport_i[25]
    DIRECTION INPUT ;
    USE SIGNAL ;
    ANTENNAGATEAREA 0.196500 ;
    PORT
      LAYER met2 ;
        RECT 143.150 0.000 143.430 4.000 ;
    END
  END mport_i[25]
  PIN mport_i[26]
    DIRECTION INPUT ;
    USE SIGNAL ;
    ANTENNAGATEAREA 0.196500 ;
    PORT
      LAYER met2 ;
        RECT 148.210 0.000 148.490 4.000 ;
    END
  END mport_i[26]
  PIN mport_i[27]
    DIRECTION INPUT ;
    USE SIGNAL ;
    ANTENNAGATEAREA 0.196500 ;
    PORT
      LAYER met2 ;
        RECT 153.270 0.000 153.550 4.000 ;
    END
  END mport_i[27]
  PIN mport_i[28]
    DIRECTION INPUT ;
    USE SIGNAL ;
    ANTENNAGATEAREA 0.196500 ;
    PORT
      LAYER met2 ;
        RECT 158.330 0.000 158.610 4.000 ;
    END
  END mport_i[28]
  PIN mport_i[29]
    DIRECTION INPUT ;
    USE SIGNAL ;
    ANTENNAGATEAREA 0.196500 ;
    PORT
      LAYER met2 ;
        RECT 163.390 0.000 163.670 4.000 ;
    END
  END mport_i[29]
  PIN mport_i[2]
    DIRECTION INPUT ;
    USE SIGNAL ;
    ANTENNAGATEAREA 0.196500 ;
    PORT
      LAYER met2 ;
        RECT 26.770 0.000 27.050 4.000 ;
    END
  END mport_i[2]
  PIN mport_i[30]
    DIRECTION INPUT ;
    USE SIGNAL ;
    ANTENNAGATEAREA 0.196500 ;
    PORT
      LAYER met2 ;
        RECT 168.450 0.000 168.730 4.000 ;
    END
  END mport_i[30]
  PIN mport_i[31]
    DIRECTION INPUT ;
    USE SIGNAL ;
    ANTENNAGATEAREA 0.196500 ;
    PORT
      LAYER met2 ;
        RECT 173.510 0.000 173.790 4.000 ;
    END
  END mport_i[31]
  PIN mport_i[32]
    DIRECTION INPUT ;
    USE SIGNAL ;
    ANTENNAGATEAREA 0.247500 ;
    PORT
      LAYER met2 ;
        RECT 178.570 0.000 178.850 4.000 ;
    END
  END mport_i[32]
  PIN mport_i[33]
    DIRECTION INPUT ;
    USE SIGNAL ;
    PORT
      LAYER met2 ;
        RECT 183.630 0.000 183.910 4.000 ;
    END
  END mport_i[33]
  PIN mport_i[3]
    DIRECTION INPUT ;
    USE SIGNAL ;
    ANTENNAGATEAREA 0.196500 ;
    PORT
      LAYER met2 ;
        RECT 31.830 0.000 32.110 4.000 ;
    END
  END mport_i[3]
  PIN mport_i[4]
    DIRECTION INPUT ;
    USE SIGNAL ;
    ANTENNAGATEAREA 0.196500 ;
    PORT
      LAYER met2 ;
        RECT 36.890 0.000 37.170 4.000 ;
    END
  END mport_i[4]
  PIN mport_i[5]
    DIRECTION INPUT ;
    USE SIGNAL ;
    ANTENNAGATEAREA 0.196500 ;
    PORT
      LAYER met2 ;
        RECT 41.950 0.000 42.230 4.000 ;
    END
  END mport_i[5]
  PIN mport_i[6]
    DIRECTION INPUT ;
    USE SIGNAL ;
    ANTENNAGATEAREA 0.196500 ;
    PORT
      LAYER met2 ;
        RECT 47.010 0.000 47.290 4.000 ;
    END
  END mport_i[6]
  PIN mport_i[7]
    DIRECTION INPUT ;
    USE SIGNAL ;
    ANTENNAGATEAREA 0.196500 ;
    PORT
      LAYER met2 ;
        RECT 52.070 0.000 52.350 4.000 ;
    END
  END mport_i[7]
  PIN mport_i[8]
    DIRECTION INPUT ;
    USE SIGNAL ;
    ANTENNAGATEAREA 0.196500 ;
    PORT
      LAYER met2 ;
        RECT 57.130 0.000 57.410 4.000 ;
    END
  END mport_i[8]
  PIN mport_i[9]
    DIRECTION INPUT ;
    USE SIGNAL ;
    ANTENNAGATEAREA 0.196500 ;
    PORT
      LAYER met2 ;
        RECT 62.190 0.000 62.470 4.000 ;
    END
  END mport_i[9]
  PIN mport_o[0]
    DIRECTION OUTPUT TRISTATE ;
    USE SIGNAL ;
    ANTENNADIFFAREA 0.795200 ;
    PORT
      LAYER met2 ;
        RECT 188.690 0.000 188.970 4.000 ;
    END
  END mport_o[0]
  PIN mport_o[10]
    DIRECTION OUTPUT TRISTATE ;
    USE SIGNAL ;
    ANTENNADIFFAREA 0.795200 ;
    PORT
      LAYER met2 ;
        RECT 239.290 0.000 239.570 4.000 ;
    END
  END mport_o[10]
  PIN mport_o[11]
    DIRECTION OUTPUT TRISTATE ;
    USE SIGNAL ;
    ANTENNADIFFAREA 0.795200 ;
    PORT
      LAYER met2 ;
        RECT 244.350 0.000 244.630 4.000 ;
    END
  END mport_o[11]
  PIN mport_o[12]
    DIRECTION OUTPUT TRISTATE ;
    USE SIGNAL ;
    ANTENNADIFFAREA 0.795200 ;
    PORT
      LAYER met2 ;
        RECT 249.410 0.000 249.690 4.000 ;
    END
  END mport_o[12]
  PIN mport_o[13]
    DIRECTION OUTPUT TRISTATE ;
    USE SIGNAL ;
    ANTENNADIFFAREA 0.795200 ;
    PORT
      LAYER met2 ;
        RECT 254.470 0.000 254.750 4.000 ;
    END
  END mport_o[13]
  PIN mport_o[14]
    DIRECTION OUTPUT TRISTATE ;
    USE SIGNAL ;
    ANTENNADIFFAREA 0.795200 ;
    PORT
      LAYER met2 ;
        RECT 259.530 0.000 259.810 4.000 ;
    END
  END mport_o[14]
  PIN mport_o[15]
    DIRECTION OUTPUT TRISTATE ;
    USE SIGNAL ;
    ANTENNADIFFAREA 0.795200 ;
    PORT
      LAYER met2 ;
        RECT 264.590 0.000 264.870 4.000 ;
    END
  END mport_o[15]
  PIN mport_o[16]
    DIRECTION OUTPUT TRISTATE ;
    USE SIGNAL ;
    ANTENNADIFFAREA 0.795200 ;
    PORT
      LAYER met2 ;
        RECT 269.650 0.000 269.930 4.000 ;
    END
  END mport_o[16]
  PIN mport_o[17]
    DIRECTION OUTPUT TRISTATE ;
    USE SIGNAL ;
    ANTENNADIFFAREA 0.795200 ;
    PORT
      LAYER met2 ;
        RECT 274.710 0.000 274.990 4.000 ;
    END
  END mport_o[17]
  PIN mport_o[18]
    DIRECTION OUTPUT TRISTATE ;
    USE SIGNAL ;
    ANTENNADIFFAREA 0.795200 ;
    PORT
      LAYER met2 ;
        RECT 279.770 0.000 280.050 4.000 ;
    END
  END mport_o[18]
  PIN mport_o[19]
    DIRECTION OUTPUT TRISTATE ;
    USE SIGNAL ;
    ANTENNADIFFAREA 0.795200 ;
    PORT
      LAYER met2 ;
        RECT 284.830 0.000 285.110 4.000 ;
    END
  END mport_o[19]
  PIN mport_o[1]
    DIRECTION OUTPUT TRISTATE ;
    USE SIGNAL ;
    ANTENNADIFFAREA 0.795200 ;
    PORT
      LAYER met2 ;
        RECT 193.750 0.000 194.030 4.000 ;
    END
  END mport_o[1]
  PIN mport_o[20]
    DIRECTION OUTPUT TRISTATE ;
    USE SIGNAL ;
    ANTENNADIFFAREA 0.795200 ;
    PORT
      LAYER met2 ;
        RECT 289.890 0.000 290.170 4.000 ;
    END
  END mport_o[20]
  PIN mport_o[21]
    DIRECTION OUTPUT TRISTATE ;
    USE SIGNAL ;
    ANTENNADIFFAREA 0.795200 ;
    PORT
      LAYER met2 ;
        RECT 294.950 0.000 295.230 4.000 ;
    END
  END mport_o[21]
  PIN mport_o[22]
    DIRECTION OUTPUT TRISTATE ;
    USE SIGNAL ;
    ANTENNADIFFAREA 0.795200 ;
    PORT
      LAYER met2 ;
        RECT 300.010 0.000 300.290 4.000 ;
    END
  END mport_o[22]
  PIN mport_o[23]
    DIRECTION OUTPUT TRISTATE ;
    USE SIGNAL ;
    ANTENNADIFFAREA 0.795200 ;
    PORT
      LAYER met2 ;
        RECT 305.070 0.000 305.350 4.000 ;
    END
  END mport_o[23]
  PIN mport_o[24]
    DIRECTION OUTPUT TRISTATE ;
    USE SIGNAL ;
    ANTENNADIFFAREA 0.795200 ;
    PORT
      LAYER met2 ;
        RECT 310.130 0.000 310.410 4.000 ;
    END
  END mport_o[24]
  PIN mport_o[25]
    DIRECTION OUTPUT TRISTATE ;
    USE SIGNAL ;
    ANTENNADIFFAREA 0.795200 ;
    PORT
      LAYER met2 ;
        RECT 315.190 0.000 315.470 4.000 ;
    END
  END mport_o[25]
  PIN mport_o[26]
    DIRECTION OUTPUT TRISTATE ;
    USE SIGNAL ;
    ANTENNADIFFAREA 0.795200 ;
    PORT
      LAYER met2 ;
        RECT 320.250 0.000 320.530 4.000 ;
    END
  END mport_o[26]
  PIN mport_o[27]
    DIRECTION OUTPUT TRISTATE ;
    USE SIGNAL ;
    ANTENNADIFFAREA 0.795200 ;
    PORT
      LAYER met2 ;
        RECT 325.310 0.000 325.590 4.000 ;
    END
  END mport_o[27]
  PIN mport_o[28]
    DIRECTION OUTPUT TRISTATE ;
    USE SIGNAL ;
    ANTENNADIFFAREA 0.795200 ;
    PORT
      LAYER met2 ;
        RECT 330.370 0.000 330.650 4.000 ;
    END
  END mport_o[28]
  PIN mport_o[29]
    DIRECTION OUTPUT TRISTATE ;
    USE SIGNAL ;
    ANTENNADIFFAREA 0.795200 ;
    PORT
      LAYER met2 ;
        RECT 335.430 0.000 335.710 4.000 ;
    END
  END mport_o[29]
  PIN mport_o[2]
    DIRECTION OUTPUT TRISTATE ;
    USE SIGNAL ;
    ANTENNADIFFAREA 0.795200 ;
    PORT
      LAYER met2 ;
        RECT 198.810 0.000 199.090 4.000 ;
    END
  END mport_o[2]
  PIN mport_o[30]
    DIRECTION OUTPUT TRISTATE ;
    USE SIGNAL ;
    ANTENNADIFFAREA 0.795200 ;
    PORT
      LAYER met2 ;
        RECT 340.490 0.000 340.770 4.000 ;
    END
  END mport_o[30]
  PIN mport_o[31]
    DIRECTION OUTPUT TRISTATE ;
    USE SIGNAL ;
    ANTENNADIFFAREA 0.795200 ;
    PORT
      LAYER met2 ;
        RECT 345.550 0.000 345.830 4.000 ;
    END
  END mport_o[31]
  PIN mport_o[32]
    DIRECTION OUTPUT TRISTATE ;
    USE SIGNAL ;
    ANTENNADIFFAREA 0.795200 ;
    PORT
      LAYER met2 ;
        RECT 350.610 0.000 350.890 4.000 ;
    END
  END mport_o[32]
  PIN mport_o[33]
    DIRECTION OUTPUT TRISTATE ;
    USE SIGNAL ;
    ANTENNADIFFAREA 0.795200 ;
    PORT
      LAYER met2 ;
        RECT 355.670 0.000 355.950 4.000 ;
    END
  END mport_o[33]
  PIN mport_o[34]
    DIRECTION OUTPUT TRISTATE ;
    USE SIGNAL ;
    ANTENNADIFFAREA 0.795200 ;
    PORT
      LAYER met2 ;
        RECT 360.730 0.000 361.010 4.000 ;
    END
  END mport_o[34]
  PIN mport_o[35]
    DIRECTION OUTPUT TRISTATE ;
    USE SIGNAL ;
    ANTENNADIFFAREA 0.795200 ;
    PORT
      LAYER met2 ;
        RECT 365.790 0.000 366.070 4.000 ;
    END
  END mport_o[35]
  PIN mport_o[36]
    DIRECTION OUTPUT TRISTATE ;
    USE SIGNAL ;
    ANTENNADIFFAREA 0.795200 ;
    PORT
      LAYER met2 ;
        RECT 370.850 0.000 371.130 4.000 ;
    END
  END mport_o[36]
  PIN mport_o[37]
    DIRECTION OUTPUT TRISTATE ;
    USE SIGNAL ;
    ANTENNADIFFAREA 0.795200 ;
    PORT
      LAYER met2 ;
        RECT 375.910 0.000 376.190 4.000 ;
    END
  END mport_o[37]
  PIN mport_o[38]
    DIRECTION OUTPUT TRISTATE ;
    USE SIGNAL ;
    ANTENNADIFFAREA 0.795200 ;
    PORT
      LAYER met2 ;
        RECT 380.970 0.000 381.250 4.000 ;
    END
  END mport_o[38]
  PIN mport_o[39]
    DIRECTION OUTPUT TRISTATE ;
    USE SIGNAL ;
    ANTENNADIFFAREA 0.795200 ;
    PORT
      LAYER met2 ;
        RECT 386.030 0.000 386.310 4.000 ;
    END
  END mport_o[39]
  PIN mport_o[3]
    DIRECTION OUTPUT TRISTATE ;
    USE SIGNAL ;
    ANTENNADIFFAREA 0.795200 ;
    PORT
      LAYER met2 ;
        RECT 203.870 0.000 204.150 4.000 ;
    END
  END mport_o[3]
  PIN mport_o[40]
    DIRECTION OUTPUT TRISTATE ;
    USE SIGNAL ;
    ANTENNADIFFAREA 0.795200 ;
    PORT
      LAYER met2 ;
        RECT 391.090 0.000 391.370 4.000 ;
    END
  END mport_o[40]
  PIN mport_o[41]
    DIRECTION OUTPUT TRISTATE ;
    USE SIGNAL ;
    ANTENNADIFFAREA 0.795200 ;
    PORT
      LAYER met2 ;
        RECT 396.150 0.000 396.430 4.000 ;
    END
  END mport_o[41]
  PIN mport_o[42]
    DIRECTION OUTPUT TRISTATE ;
    USE SIGNAL ;
    ANTENNADIFFAREA 0.795200 ;
    PORT
      LAYER met2 ;
        RECT 401.210 0.000 401.490 4.000 ;
    END
  END mport_o[42]
  PIN mport_o[43]
    DIRECTION OUTPUT TRISTATE ;
    USE SIGNAL ;
    ANTENNADIFFAREA 0.795200 ;
    PORT
      LAYER met2 ;
        RECT 406.270 0.000 406.550 4.000 ;
    END
  END mport_o[43]
  PIN mport_o[44]
    DIRECTION OUTPUT TRISTATE ;
    USE SIGNAL ;
    ANTENNADIFFAREA 0.795200 ;
    PORT
      LAYER met2 ;
        RECT 411.330 0.000 411.610 4.000 ;
    END
  END mport_o[44]
  PIN mport_o[45]
    DIRECTION OUTPUT TRISTATE ;
    USE SIGNAL ;
    ANTENNADIFFAREA 0.795200 ;
    PORT
      LAYER met2 ;
        RECT 416.390 0.000 416.670 4.000 ;
    END
  END mport_o[45]
  PIN mport_o[46]
    DIRECTION OUTPUT TRISTATE ;
    USE SIGNAL ;
    ANTENNADIFFAREA 0.795200 ;
    PORT
      LAYER met2 ;
        RECT 421.450 0.000 421.730 4.000 ;
    END
  END mport_o[46]
  PIN mport_o[47]
    DIRECTION OUTPUT TRISTATE ;
    USE SIGNAL ;
    ANTENNADIFFAREA 0.795200 ;
    PORT
      LAYER met2 ;
        RECT 426.510 0.000 426.790 4.000 ;
    END
  END mport_o[47]
  PIN mport_o[48]
    DIRECTION OUTPUT TRISTATE ;
    USE SIGNAL ;
    ANTENNADIFFAREA 0.795200 ;
    PORT
      LAYER met2 ;
        RECT 431.570 0.000 431.850 4.000 ;
    END
  END mport_o[48]
  PIN mport_o[49]
    DIRECTION OUTPUT TRISTATE ;
    USE SIGNAL ;
    ANTENNADIFFAREA 0.795200 ;
    PORT
      LAYER met2 ;
        RECT 436.630 0.000 436.910 4.000 ;
    END
  END mport_o[49]
  PIN mport_o[4]
    DIRECTION OUTPUT TRISTATE ;
    USE SIGNAL ;
    ANTENNADIFFAREA 0.795200 ;
    PORT
      LAYER met2 ;
        RECT 208.930 0.000 209.210 4.000 ;
    END
  END mport_o[4]
  PIN mport_o[50]
    DIRECTION OUTPUT TRISTATE ;
    USE SIGNAL ;
    ANTENNADIFFAREA 0.795200 ;
    PORT
      LAYER met2 ;
        RECT 441.690 0.000 441.970 4.000 ;
    END
  END mport_o[50]
  PIN mport_o[51]
    DIRECTION OUTPUT TRISTATE ;
    USE SIGNAL ;
    ANTENNADIFFAREA 0.795200 ;
    PORT
      LAYER met2 ;
        RECT 446.750 0.000 447.030 4.000 ;
    END
  END mport_o[51]
  PIN mport_o[52]
    DIRECTION OUTPUT TRISTATE ;
    USE SIGNAL ;
    ANTENNADIFFAREA 0.795200 ;
    PORT
      LAYER met2 ;
        RECT 451.810 0.000 452.090 4.000 ;
    END
  END mport_o[52]
  PIN mport_o[53]
    DIRECTION OUTPUT TRISTATE ;
    USE SIGNAL ;
    ANTENNADIFFAREA 0.795200 ;
    PORT
      LAYER met2 ;
        RECT 456.870 0.000 457.150 4.000 ;
    END
  END mport_o[53]
  PIN mport_o[54]
    DIRECTION OUTPUT TRISTATE ;
    USE SIGNAL ;
    ANTENNADIFFAREA 0.795200 ;
    PORT
      LAYER met2 ;
        RECT 461.930 0.000 462.210 4.000 ;
    END
  END mport_o[54]
  PIN mport_o[55]
    DIRECTION OUTPUT TRISTATE ;
    USE SIGNAL ;
    ANTENNADIFFAREA 0.795200 ;
    PORT
      LAYER met2 ;
        RECT 466.990 0.000 467.270 4.000 ;
    END
  END mport_o[55]
  PIN mport_o[56]
    DIRECTION OUTPUT TRISTATE ;
    USE SIGNAL ;
    ANTENNADIFFAREA 0.795200 ;
    PORT
      LAYER met2 ;
        RECT 472.050 0.000 472.330 4.000 ;
    END
  END mport_o[56]
  PIN mport_o[57]
    DIRECTION OUTPUT TRISTATE ;
    USE SIGNAL ;
    ANTENNADIFFAREA 0.795200 ;
    PORT
      LAYER met2 ;
        RECT 477.110 0.000 477.390 4.000 ;
    END
  END mport_o[57]
  PIN mport_o[58]
    DIRECTION OUTPUT TRISTATE ;
    USE SIGNAL ;
    ANTENNADIFFAREA 0.795200 ;
    PORT
      LAYER met2 ;
        RECT 482.170 0.000 482.450 4.000 ;
    END
  END mport_o[58]
  PIN mport_o[59]
    DIRECTION OUTPUT TRISTATE ;
    USE SIGNAL ;
    ANTENNADIFFAREA 0.795200 ;
    PORT
      LAYER met2 ;
        RECT 487.230 0.000 487.510 4.000 ;
    END
  END mport_o[59]
  PIN mport_o[5]
    DIRECTION OUTPUT TRISTATE ;
    USE SIGNAL ;
    ANTENNADIFFAREA 0.795200 ;
    PORT
      LAYER met2 ;
        RECT 213.990 0.000 214.270 4.000 ;
    END
  END mport_o[5]
  PIN mport_o[60]
    DIRECTION OUTPUT TRISTATE ;
    USE SIGNAL ;
    ANTENNADIFFAREA 0.795200 ;
    PORT
      LAYER met2 ;
        RECT 492.290 0.000 492.570 4.000 ;
    END
  END mport_o[60]
  PIN mport_o[61]
    DIRECTION OUTPUT TRISTATE ;
    USE SIGNAL ;
    ANTENNADIFFAREA 0.795200 ;
    PORT
      LAYER met2 ;
        RECT 497.350 0.000 497.630 4.000 ;
    END
  END mport_o[61]
  PIN mport_o[62]
    DIRECTION OUTPUT TRISTATE ;
    USE SIGNAL ;
    ANTENNADIFFAREA 0.795200 ;
    PORT
      LAYER met2 ;
        RECT 502.410 0.000 502.690 4.000 ;
    END
  END mport_o[62]
  PIN mport_o[63]
    DIRECTION OUTPUT TRISTATE ;
    USE SIGNAL ;
    ANTENNADIFFAREA 0.795200 ;
    PORT
      LAYER met2 ;
        RECT 507.470 0.000 507.750 4.000 ;
    END
  END mport_o[63]
  PIN mport_o[64]
    DIRECTION OUTPUT TRISTATE ;
    USE SIGNAL ;
    ANTENNADIFFAREA 0.795200 ;
    PORT
      LAYER met2 ;
        RECT 512.530 0.000 512.810 4.000 ;
    END
  END mport_o[64]
  PIN mport_o[65]
    DIRECTION OUTPUT TRISTATE ;
    USE SIGNAL ;
    PORT
      LAYER met2 ;
        RECT 517.590 0.000 517.870 4.000 ;
    END
  END mport_o[65]
  PIN mport_o[66]
    DIRECTION OUTPUT TRISTATE ;
    USE SIGNAL ;
    ANTENNADIFFAREA 0.795200 ;
    PORT
      LAYER met2 ;
        RECT 522.650 0.000 522.930 4.000 ;
    END
  END mport_o[66]
  PIN mport_o[67]
    DIRECTION OUTPUT TRISTATE ;
    USE SIGNAL ;
    PORT
      LAYER met2 ;
        RECT 527.710 0.000 527.990 4.000 ;
    END
  END mport_o[67]
  PIN mport_o[68]
    DIRECTION OUTPUT TRISTATE ;
    USE SIGNAL ;
    ANTENNADIFFAREA 0.795200 ;
    PORT
      LAYER met2 ;
        RECT 532.770 0.000 533.050 4.000 ;
    END
  END mport_o[68]
  PIN mport_o[6]
    DIRECTION OUTPUT TRISTATE ;
    USE SIGNAL ;
    ANTENNADIFFAREA 0.795200 ;
    PORT
      LAYER met2 ;
        RECT 219.050 0.000 219.330 4.000 ;
    END
  END mport_o[6]
  PIN mport_o[7]
    DIRECTION OUTPUT TRISTATE ;
    USE SIGNAL ;
    ANTENNADIFFAREA 0.795200 ;
    PORT
      LAYER met2 ;
        RECT 224.110 0.000 224.390 4.000 ;
    END
  END mport_o[7]
  PIN mport_o[8]
    DIRECTION OUTPUT TRISTATE ;
    USE SIGNAL ;
    ANTENNADIFFAREA 0.795200 ;
    PORT
      LAYER met2 ;
        RECT 229.170 0.000 229.450 4.000 ;
    END
  END mport_o[8]
  PIN mport_o[9]
    DIRECTION OUTPUT TRISTATE ;
    USE SIGNAL ;
    ANTENNADIFFAREA 0.795200 ;
    PORT
      LAYER met2 ;
        RECT 234.230 0.000 234.510 4.000 ;
    END
  END mport_o[9]
  PIN nrst_i
    DIRECTION INPUT ;
    USE SIGNAL ;
    ANTENNAGATEAREA 0.426000 ;
    PORT
      LAYER met3 ;
        RECT 0.000 16.360 4.000 16.960 ;
    END
  END nrst_i
  PIN nsync_rst_i
    DIRECTION INPUT ;
    USE SIGNAL ;
    ANTENNAGATEAREA 0.196500 ;
    PORT
      LAYER met3 ;
        RECT 546.000 512.760 550.000 513.360 ;
    END
  END nsync_rst_i
  PIN nsync_rst_mailbox_i
    DIRECTION INPUT ;
    USE SIGNAL ;
    ANTENNAGATEAREA 0.196500 ;
    PORT
      LAYER met3 ;
        RECT 546.000 519.560 550.000 520.160 ;
    END
  END nsync_rst_mailbox_i
  PIN outbox_mstream_i
    DIRECTION INPUT ;
    USE SIGNAL ;
    ANTENNAGATEAREA 0.213000 ;
    PORT
      LAYER met2 ;
        RECT 8.830 546.000 9.110 550.000 ;
    END
  END outbox_mstream_i
  PIN outbox_mstream_o[0]
    DIRECTION OUTPUT TRISTATE ;
    USE SIGNAL ;
    ANTENNADIFFAREA 0.795200 ;
    PORT
      LAYER met2 ;
        RECT 24.470 546.000 24.750 550.000 ;
    END
  END outbox_mstream_o[0]
  PIN outbox_mstream_o[10]
    DIRECTION OUTPUT TRISTATE ;
    USE SIGNAL ;
    ANTENNADIFFAREA 0.795200 ;
    PORT
      LAYER met2 ;
        RECT 180.870 546.000 181.150 550.000 ;
    END
  END outbox_mstream_o[10]
  PIN outbox_mstream_o[11]
    DIRECTION OUTPUT TRISTATE ;
    USE SIGNAL ;
    ANTENNADIFFAREA 0.795200 ;
    PORT
      LAYER met2 ;
        RECT 196.510 546.000 196.790 550.000 ;
    END
  END outbox_mstream_o[11]
  PIN outbox_mstream_o[12]
    DIRECTION OUTPUT TRISTATE ;
    USE SIGNAL ;
    ANTENNADIFFAREA 0.795200 ;
    PORT
      LAYER met2 ;
        RECT 212.150 546.000 212.430 550.000 ;
    END
  END outbox_mstream_o[12]
  PIN outbox_mstream_o[13]
    DIRECTION OUTPUT TRISTATE ;
    USE SIGNAL ;
    ANTENNADIFFAREA 0.795200 ;
    PORT
      LAYER met2 ;
        RECT 227.790 546.000 228.070 550.000 ;
    END
  END outbox_mstream_o[13]
  PIN outbox_mstream_o[14]
    DIRECTION OUTPUT TRISTATE ;
    USE SIGNAL ;
    ANTENNADIFFAREA 0.795200 ;
    PORT
      LAYER met2 ;
        RECT 243.430 546.000 243.710 550.000 ;
    END
  END outbox_mstream_o[14]
  PIN outbox_mstream_o[15]
    DIRECTION OUTPUT TRISTATE ;
    USE SIGNAL ;
    ANTENNADIFFAREA 0.795200 ;
    PORT
      LAYER met2 ;
        RECT 259.070 546.000 259.350 550.000 ;
    END
  END outbox_mstream_o[15]
  PIN outbox_mstream_o[16]
    DIRECTION OUTPUT TRISTATE ;
    USE SIGNAL ;
    ANTENNADIFFAREA 0.795200 ;
    PORT
      LAYER met2 ;
        RECT 274.710 546.000 274.990 550.000 ;
    END
  END outbox_mstream_o[16]
  PIN outbox_mstream_o[17]
    DIRECTION OUTPUT TRISTATE ;
    USE SIGNAL ;
    ANTENNADIFFAREA 0.795200 ;
    PORT
      LAYER met2 ;
        RECT 290.350 546.000 290.630 550.000 ;
    END
  END outbox_mstream_o[17]
  PIN outbox_mstream_o[18]
    DIRECTION OUTPUT TRISTATE ;
    USE SIGNAL ;
    ANTENNADIFFAREA 0.795200 ;
    PORT
      LAYER met2 ;
        RECT 305.990 546.000 306.270 550.000 ;
    END
  END outbox_mstream_o[18]
  PIN outbox_mstream_o[19]
    DIRECTION OUTPUT TRISTATE ;
    USE SIGNAL ;
    ANTENNADIFFAREA 0.795200 ;
    PORT
      LAYER met2 ;
        RECT 321.630 546.000 321.910 550.000 ;
    END
  END outbox_mstream_o[19]
  PIN outbox_mstream_o[1]
    DIRECTION OUTPUT TRISTATE ;
    USE SIGNAL ;
    ANTENNADIFFAREA 0.795200 ;
    PORT
      LAYER met2 ;
        RECT 40.110 546.000 40.390 550.000 ;
    END
  END outbox_mstream_o[1]
  PIN outbox_mstream_o[20]
    DIRECTION OUTPUT TRISTATE ;
    USE SIGNAL ;
    ANTENNADIFFAREA 0.795200 ;
    PORT
      LAYER met2 ;
        RECT 337.270 546.000 337.550 550.000 ;
    END
  END outbox_mstream_o[20]
  PIN outbox_mstream_o[21]
    DIRECTION OUTPUT TRISTATE ;
    USE SIGNAL ;
    ANTENNADIFFAREA 0.795200 ;
    PORT
      LAYER met2 ;
        RECT 352.910 546.000 353.190 550.000 ;
    END
  END outbox_mstream_o[21]
  PIN outbox_mstream_o[22]
    DIRECTION OUTPUT TRISTATE ;
    USE SIGNAL ;
    ANTENNADIFFAREA 0.795200 ;
    PORT
      LAYER met2 ;
        RECT 368.550 546.000 368.830 550.000 ;
    END
  END outbox_mstream_o[22]
  PIN outbox_mstream_o[23]
    DIRECTION OUTPUT TRISTATE ;
    USE SIGNAL ;
    ANTENNADIFFAREA 0.795200 ;
    PORT
      LAYER met2 ;
        RECT 384.190 546.000 384.470 550.000 ;
    END
  END outbox_mstream_o[23]
  PIN outbox_mstream_o[24]
    DIRECTION OUTPUT TRISTATE ;
    USE SIGNAL ;
    ANTENNADIFFAREA 0.795200 ;
    PORT
      LAYER met2 ;
        RECT 399.830 546.000 400.110 550.000 ;
    END
  END outbox_mstream_o[24]
  PIN outbox_mstream_o[25]
    DIRECTION OUTPUT TRISTATE ;
    USE SIGNAL ;
    ANTENNADIFFAREA 0.795200 ;
    PORT
      LAYER met2 ;
        RECT 415.470 546.000 415.750 550.000 ;
    END
  END outbox_mstream_o[25]
  PIN outbox_mstream_o[26]
    DIRECTION OUTPUT TRISTATE ;
    USE SIGNAL ;
    ANTENNADIFFAREA 0.795200 ;
    PORT
      LAYER met2 ;
        RECT 431.110 546.000 431.390 550.000 ;
    END
  END outbox_mstream_o[26]
  PIN outbox_mstream_o[27]
    DIRECTION OUTPUT TRISTATE ;
    USE SIGNAL ;
    ANTENNADIFFAREA 0.795200 ;
    PORT
      LAYER met2 ;
        RECT 446.750 546.000 447.030 550.000 ;
    END
  END outbox_mstream_o[27]
  PIN outbox_mstream_o[28]
    DIRECTION OUTPUT TRISTATE ;
    USE SIGNAL ;
    ANTENNADIFFAREA 0.795200 ;
    PORT
      LAYER met2 ;
        RECT 462.390 546.000 462.670 550.000 ;
    END
  END outbox_mstream_o[28]
  PIN outbox_mstream_o[29]
    DIRECTION OUTPUT TRISTATE ;
    USE SIGNAL ;
    ANTENNADIFFAREA 0.795200 ;
    PORT
      LAYER met2 ;
        RECT 478.030 546.000 478.310 550.000 ;
    END
  END outbox_mstream_o[29]
  PIN outbox_mstream_o[2]
    DIRECTION OUTPUT TRISTATE ;
    USE SIGNAL ;
    ANTENNADIFFAREA 0.795200 ;
    PORT
      LAYER met2 ;
        RECT 55.750 546.000 56.030 550.000 ;
    END
  END outbox_mstream_o[2]
  PIN outbox_mstream_o[30]
    DIRECTION OUTPUT TRISTATE ;
    USE SIGNAL ;
    ANTENNADIFFAREA 0.795200 ;
    PORT
      LAYER met2 ;
        RECT 493.670 546.000 493.950 550.000 ;
    END
  END outbox_mstream_o[30]
  PIN outbox_mstream_o[31]
    DIRECTION OUTPUT TRISTATE ;
    USE SIGNAL ;
    ANTENNADIFFAREA 0.795200 ;
    PORT
      LAYER met2 ;
        RECT 509.310 546.000 509.590 550.000 ;
    END
  END outbox_mstream_o[31]
  PIN outbox_mstream_o[32]
    DIRECTION OUTPUT TRISTATE ;
    USE SIGNAL ;
    ANTENNADIFFAREA 0.795200 ;
    PORT
      LAYER met2 ;
        RECT 524.950 546.000 525.230 550.000 ;
    END
  END outbox_mstream_o[32]
  PIN outbox_mstream_o[33]
    DIRECTION OUTPUT TRISTATE ;
    USE SIGNAL ;
    PORT
      LAYER met2 ;
        RECT 540.590 546.000 540.870 550.000 ;
    END
  END outbox_mstream_o[33]
  PIN outbox_mstream_o[3]
    DIRECTION OUTPUT TRISTATE ;
    USE SIGNAL ;
    ANTENNADIFFAREA 0.795200 ;
    PORT
      LAYER met2 ;
        RECT 71.390 546.000 71.670 550.000 ;
    END
  END outbox_mstream_o[3]
  PIN outbox_mstream_o[4]
    DIRECTION OUTPUT TRISTATE ;
    USE SIGNAL ;
    ANTENNADIFFAREA 0.795200 ;
    PORT
      LAYER met2 ;
        RECT 87.030 546.000 87.310 550.000 ;
    END
  END outbox_mstream_o[4]
  PIN outbox_mstream_o[5]
    DIRECTION OUTPUT TRISTATE ;
    USE SIGNAL ;
    ANTENNADIFFAREA 0.795200 ;
    PORT
      LAYER met2 ;
        RECT 102.670 546.000 102.950 550.000 ;
    END
  END outbox_mstream_o[5]
  PIN outbox_mstream_o[6]
    DIRECTION OUTPUT TRISTATE ;
    USE SIGNAL ;
    ANTENNADIFFAREA 0.795200 ;
    PORT
      LAYER met2 ;
        RECT 118.310 546.000 118.590 550.000 ;
    END
  END outbox_mstream_o[6]
  PIN outbox_mstream_o[7]
    DIRECTION OUTPUT TRISTATE ;
    USE SIGNAL ;
    ANTENNADIFFAREA 0.795200 ;
    PORT
      LAYER met2 ;
        RECT 133.950 546.000 134.230 550.000 ;
    END
  END outbox_mstream_o[7]
  PIN outbox_mstream_o[8]
    DIRECTION OUTPUT TRISTATE ;
    USE SIGNAL ;
    ANTENNADIFFAREA 0.795200 ;
    PORT
      LAYER met2 ;
        RECT 149.590 546.000 149.870 550.000 ;
    END
  END outbox_mstream_o[8]
  PIN outbox_mstream_o[9]
    DIRECTION OUTPUT TRISTATE ;
    USE SIGNAL ;
    ANTENNADIFFAREA 0.795200 ;
    PORT
      LAYER met2 ;
        RECT 165.230 546.000 165.510 550.000 ;
    END
  END outbox_mstream_o[9]
  PIN stall_i
    DIRECTION INPUT ;
    USE SIGNAL ;
    ANTENNAGATEAREA 0.196500 ;
    PORT
      LAYER met3 ;
        RECT 546.000 499.160 550.000 499.760 ;
    END
  END stall_i
  PIN stall_o
    DIRECTION OUTPUT TRISTATE ;
    USE SIGNAL ;
    ANTENNADIFFAREA 0.445500 ;
    PORT
      LAYER met3 ;
        RECT 546.000 505.960 550.000 506.560 ;
    END
  END stall_o
  PIN vccd1
    DIRECTION INOUT ;
    USE POWER ;
    PORT
      LAYER met4 ;
        RECT -2.080 3.280 -0.480 546.160 ;
    END
    PORT
      LAYER met5 ;
        RECT -2.080 3.280 551.780 4.880 ;
    END
    PORT
      LAYER met5 ;
        RECT -2.080 544.560 551.780 546.160 ;
    END
    PORT
      LAYER met4 ;
        RECT 550.180 3.280 551.780 546.160 ;
    END
    PORT
      LAYER met4 ;
        RECT 21.040 -0.020 22.640 549.460 ;
    END
    PORT
      LAYER met4 ;
        RECT 174.640 -0.020 176.240 549.460 ;
    END
    PORT
      LAYER met4 ;
        RECT 328.240 -0.020 329.840 549.460 ;
    END
    PORT
      LAYER met4 ;
        RECT 481.840 -0.020 483.440 549.460 ;
    END
    PORT
      LAYER met5 ;
        RECT -5.380 26.730 555.080 28.330 ;
    END
    PORT
      LAYER met5 ;
        RECT -5.380 179.910 555.080 181.510 ;
    END
    PORT
      LAYER met5 ;
        RECT -5.380 333.090 555.080 334.690 ;
    END
    PORT
      LAYER met5 ;
        RECT -5.380 486.270 555.080 487.870 ;
    END
  END vccd1
  PIN vssd1
    DIRECTION INOUT ;
    USE GROUND ;
    PORT
      LAYER met4 ;
        RECT -5.380 -0.020 -3.780 549.460 ;
    END
    PORT
      LAYER met5 ;
        RECT -5.380 -0.020 555.080 1.580 ;
    END
    PORT
      LAYER met5 ;
        RECT -5.380 547.860 555.080 549.460 ;
    END
    PORT
      LAYER met4 ;
        RECT 553.480 -0.020 555.080 549.460 ;
    END
    PORT
      LAYER met4 ;
        RECT 24.340 -0.020 25.940 549.460 ;
    END
    PORT
      LAYER met4 ;
        RECT 177.940 -0.020 179.540 549.460 ;
    END
    PORT
      LAYER met4 ;
        RECT 331.540 -0.020 333.140 549.460 ;
    END
    PORT
      LAYER met4 ;
        RECT 485.140 -0.020 486.740 549.460 ;
    END
    PORT
      LAYER met5 ;
        RECT -5.380 30.030 555.080 31.630 ;
    END
    PORT
      LAYER met5 ;
        RECT -5.380 183.210 555.080 184.810 ;
    END
    PORT
      LAYER met5 ;
        RECT -5.380 336.390 555.080 337.990 ;
    END
    PORT
      LAYER met5 ;
        RECT -5.380 489.570 555.080 491.170 ;
    END
  END vssd1
  OBS
      LAYER li1 ;
        RECT 5.520 10.795 544.180 538.645 ;
      LAYER met1 ;
        RECT 4.670 5.480 546.870 541.580 ;
      LAYER met2 ;
        RECT 4.690 545.720 8.550 546.450 ;
        RECT 9.390 545.720 24.190 546.450 ;
        RECT 25.030 545.720 39.830 546.450 ;
        RECT 40.670 545.720 55.470 546.450 ;
        RECT 56.310 545.720 71.110 546.450 ;
        RECT 71.950 545.720 86.750 546.450 ;
        RECT 87.590 545.720 102.390 546.450 ;
        RECT 103.230 545.720 118.030 546.450 ;
        RECT 118.870 545.720 133.670 546.450 ;
        RECT 134.510 545.720 149.310 546.450 ;
        RECT 150.150 545.720 164.950 546.450 ;
        RECT 165.790 545.720 180.590 546.450 ;
        RECT 181.430 545.720 196.230 546.450 ;
        RECT 197.070 545.720 211.870 546.450 ;
        RECT 212.710 545.720 227.510 546.450 ;
        RECT 228.350 545.720 243.150 546.450 ;
        RECT 243.990 545.720 258.790 546.450 ;
        RECT 259.630 545.720 274.430 546.450 ;
        RECT 275.270 545.720 290.070 546.450 ;
        RECT 290.910 545.720 305.710 546.450 ;
        RECT 306.550 545.720 321.350 546.450 ;
        RECT 322.190 545.720 336.990 546.450 ;
        RECT 337.830 545.720 352.630 546.450 ;
        RECT 353.470 545.720 368.270 546.450 ;
        RECT 369.110 545.720 383.910 546.450 ;
        RECT 384.750 545.720 399.550 546.450 ;
        RECT 400.390 545.720 415.190 546.450 ;
        RECT 416.030 545.720 430.830 546.450 ;
        RECT 431.670 545.720 446.470 546.450 ;
        RECT 447.310 545.720 462.110 546.450 ;
        RECT 462.950 545.720 477.750 546.450 ;
        RECT 478.590 545.720 493.390 546.450 ;
        RECT 494.230 545.720 509.030 546.450 ;
        RECT 509.870 545.720 524.670 546.450 ;
        RECT 525.510 545.720 540.310 546.450 ;
        RECT 541.150 545.720 546.840 546.450 ;
        RECT 4.690 4.280 546.840 545.720 ;
        RECT 4.690 3.670 16.370 4.280 ;
        RECT 17.210 3.670 21.430 4.280 ;
        RECT 22.270 3.670 26.490 4.280 ;
        RECT 27.330 3.670 31.550 4.280 ;
        RECT 32.390 3.670 36.610 4.280 ;
        RECT 37.450 3.670 41.670 4.280 ;
        RECT 42.510 3.670 46.730 4.280 ;
        RECT 47.570 3.670 51.790 4.280 ;
        RECT 52.630 3.670 56.850 4.280 ;
        RECT 57.690 3.670 61.910 4.280 ;
        RECT 62.750 3.670 66.970 4.280 ;
        RECT 67.810 3.670 72.030 4.280 ;
        RECT 72.870 3.670 77.090 4.280 ;
        RECT 77.930 3.670 82.150 4.280 ;
        RECT 82.990 3.670 87.210 4.280 ;
        RECT 88.050 3.670 92.270 4.280 ;
        RECT 93.110 3.670 97.330 4.280 ;
        RECT 98.170 3.670 102.390 4.280 ;
        RECT 103.230 3.670 107.450 4.280 ;
        RECT 108.290 3.670 112.510 4.280 ;
        RECT 113.350 3.670 117.570 4.280 ;
        RECT 118.410 3.670 122.630 4.280 ;
        RECT 123.470 3.670 127.690 4.280 ;
        RECT 128.530 3.670 132.750 4.280 ;
        RECT 133.590 3.670 137.810 4.280 ;
        RECT 138.650 3.670 142.870 4.280 ;
        RECT 143.710 3.670 147.930 4.280 ;
        RECT 148.770 3.670 152.990 4.280 ;
        RECT 153.830 3.670 158.050 4.280 ;
        RECT 158.890 3.670 163.110 4.280 ;
        RECT 163.950 3.670 168.170 4.280 ;
        RECT 169.010 3.670 173.230 4.280 ;
        RECT 174.070 3.670 178.290 4.280 ;
        RECT 179.130 3.670 183.350 4.280 ;
        RECT 184.190 3.670 188.410 4.280 ;
        RECT 189.250 3.670 193.470 4.280 ;
        RECT 194.310 3.670 198.530 4.280 ;
        RECT 199.370 3.670 203.590 4.280 ;
        RECT 204.430 3.670 208.650 4.280 ;
        RECT 209.490 3.670 213.710 4.280 ;
        RECT 214.550 3.670 218.770 4.280 ;
        RECT 219.610 3.670 223.830 4.280 ;
        RECT 224.670 3.670 228.890 4.280 ;
        RECT 229.730 3.670 233.950 4.280 ;
        RECT 234.790 3.670 239.010 4.280 ;
        RECT 239.850 3.670 244.070 4.280 ;
        RECT 244.910 3.670 249.130 4.280 ;
        RECT 249.970 3.670 254.190 4.280 ;
        RECT 255.030 3.670 259.250 4.280 ;
        RECT 260.090 3.670 264.310 4.280 ;
        RECT 265.150 3.670 269.370 4.280 ;
        RECT 270.210 3.670 274.430 4.280 ;
        RECT 275.270 3.670 279.490 4.280 ;
        RECT 280.330 3.670 284.550 4.280 ;
        RECT 285.390 3.670 289.610 4.280 ;
        RECT 290.450 3.670 294.670 4.280 ;
        RECT 295.510 3.670 299.730 4.280 ;
        RECT 300.570 3.670 304.790 4.280 ;
        RECT 305.630 3.670 309.850 4.280 ;
        RECT 310.690 3.670 314.910 4.280 ;
        RECT 315.750 3.670 319.970 4.280 ;
        RECT 320.810 3.670 325.030 4.280 ;
        RECT 325.870 3.670 330.090 4.280 ;
        RECT 330.930 3.670 335.150 4.280 ;
        RECT 335.990 3.670 340.210 4.280 ;
        RECT 341.050 3.670 345.270 4.280 ;
        RECT 346.110 3.670 350.330 4.280 ;
        RECT 351.170 3.670 355.390 4.280 ;
        RECT 356.230 3.670 360.450 4.280 ;
        RECT 361.290 3.670 365.510 4.280 ;
        RECT 366.350 3.670 370.570 4.280 ;
        RECT 371.410 3.670 375.630 4.280 ;
        RECT 376.470 3.670 380.690 4.280 ;
        RECT 381.530 3.670 385.750 4.280 ;
        RECT 386.590 3.670 390.810 4.280 ;
        RECT 391.650 3.670 395.870 4.280 ;
        RECT 396.710 3.670 400.930 4.280 ;
        RECT 401.770 3.670 405.990 4.280 ;
        RECT 406.830 3.670 411.050 4.280 ;
        RECT 411.890 3.670 416.110 4.280 ;
        RECT 416.950 3.670 421.170 4.280 ;
        RECT 422.010 3.670 426.230 4.280 ;
        RECT 427.070 3.670 431.290 4.280 ;
        RECT 432.130 3.670 436.350 4.280 ;
        RECT 437.190 3.670 441.410 4.280 ;
        RECT 442.250 3.670 446.470 4.280 ;
        RECT 447.310 3.670 451.530 4.280 ;
        RECT 452.370 3.670 456.590 4.280 ;
        RECT 457.430 3.670 461.650 4.280 ;
        RECT 462.490 3.670 466.710 4.280 ;
        RECT 467.550 3.670 471.770 4.280 ;
        RECT 472.610 3.670 476.830 4.280 ;
        RECT 477.670 3.670 481.890 4.280 ;
        RECT 482.730 3.670 486.950 4.280 ;
        RECT 487.790 3.670 492.010 4.280 ;
        RECT 492.850 3.670 497.070 4.280 ;
        RECT 497.910 3.670 502.130 4.280 ;
        RECT 502.970 3.670 507.190 4.280 ;
        RECT 508.030 3.670 512.250 4.280 ;
        RECT 513.090 3.670 517.310 4.280 ;
        RECT 518.150 3.670 522.370 4.280 ;
        RECT 523.210 3.670 527.430 4.280 ;
        RECT 528.270 3.670 532.490 4.280 ;
        RECT 533.330 3.670 546.840 4.280 ;
      LAYER met3 ;
        RECT 4.400 538.200 546.000 539.050 ;
        RECT 3.990 534.160 546.000 538.200 ;
        RECT 4.400 532.760 546.000 534.160 ;
        RECT 3.990 528.720 546.000 532.760 ;
        RECT 4.400 527.320 546.000 528.720 ;
        RECT 3.990 523.280 546.000 527.320 ;
        RECT 4.400 521.880 546.000 523.280 ;
        RECT 3.990 520.560 546.000 521.880 ;
        RECT 3.990 519.160 545.600 520.560 ;
        RECT 3.990 517.840 546.000 519.160 ;
        RECT 4.400 516.440 546.000 517.840 ;
        RECT 3.990 513.760 546.000 516.440 ;
        RECT 3.990 512.400 545.600 513.760 ;
        RECT 4.400 512.360 545.600 512.400 ;
        RECT 4.400 511.000 546.000 512.360 ;
        RECT 3.990 506.960 546.000 511.000 ;
        RECT 4.400 505.560 545.600 506.960 ;
        RECT 3.990 501.520 546.000 505.560 ;
        RECT 4.400 500.160 546.000 501.520 ;
        RECT 4.400 500.120 545.600 500.160 ;
        RECT 3.990 498.760 545.600 500.120 ;
        RECT 3.990 496.080 546.000 498.760 ;
        RECT 4.400 494.680 546.000 496.080 ;
        RECT 3.990 493.360 546.000 494.680 ;
        RECT 3.990 491.960 545.600 493.360 ;
        RECT 3.990 490.640 546.000 491.960 ;
        RECT 4.400 489.240 546.000 490.640 ;
        RECT 3.990 486.560 546.000 489.240 ;
        RECT 3.990 485.200 545.600 486.560 ;
        RECT 4.400 485.160 545.600 485.200 ;
        RECT 4.400 483.800 546.000 485.160 ;
        RECT 3.990 479.760 546.000 483.800 ;
        RECT 4.400 478.360 545.600 479.760 ;
        RECT 3.990 474.320 546.000 478.360 ;
        RECT 4.400 472.960 546.000 474.320 ;
        RECT 4.400 472.920 545.600 472.960 ;
        RECT 3.990 471.560 545.600 472.920 ;
        RECT 3.990 468.880 546.000 471.560 ;
        RECT 4.400 467.480 546.000 468.880 ;
        RECT 3.990 466.160 546.000 467.480 ;
        RECT 3.990 464.760 545.600 466.160 ;
        RECT 3.990 463.440 546.000 464.760 ;
        RECT 4.400 462.040 546.000 463.440 ;
        RECT 3.990 459.360 546.000 462.040 ;
        RECT 3.990 458.000 545.600 459.360 ;
        RECT 4.400 457.960 545.600 458.000 ;
        RECT 4.400 456.600 546.000 457.960 ;
        RECT 3.990 452.560 546.000 456.600 ;
        RECT 4.400 451.160 545.600 452.560 ;
        RECT 3.990 447.120 546.000 451.160 ;
        RECT 4.400 445.760 546.000 447.120 ;
        RECT 4.400 445.720 545.600 445.760 ;
        RECT 3.990 444.360 545.600 445.720 ;
        RECT 3.990 441.680 546.000 444.360 ;
        RECT 4.400 440.280 546.000 441.680 ;
        RECT 3.990 438.960 546.000 440.280 ;
        RECT 3.990 437.560 545.600 438.960 ;
        RECT 3.990 436.240 546.000 437.560 ;
        RECT 4.400 434.840 546.000 436.240 ;
        RECT 3.990 432.160 546.000 434.840 ;
        RECT 3.990 430.800 545.600 432.160 ;
        RECT 4.400 430.760 545.600 430.800 ;
        RECT 4.400 429.400 546.000 430.760 ;
        RECT 3.990 425.360 546.000 429.400 ;
        RECT 4.400 423.960 545.600 425.360 ;
        RECT 3.990 419.920 546.000 423.960 ;
        RECT 4.400 418.560 546.000 419.920 ;
        RECT 4.400 418.520 545.600 418.560 ;
        RECT 3.990 417.160 545.600 418.520 ;
        RECT 3.990 414.480 546.000 417.160 ;
        RECT 4.400 413.080 546.000 414.480 ;
        RECT 3.990 411.760 546.000 413.080 ;
        RECT 3.990 410.360 545.600 411.760 ;
        RECT 3.990 409.040 546.000 410.360 ;
        RECT 4.400 407.640 546.000 409.040 ;
        RECT 3.990 404.960 546.000 407.640 ;
        RECT 3.990 403.600 545.600 404.960 ;
        RECT 4.400 403.560 545.600 403.600 ;
        RECT 4.400 402.200 546.000 403.560 ;
        RECT 3.990 398.160 546.000 402.200 ;
        RECT 4.400 396.760 545.600 398.160 ;
        RECT 3.990 392.720 546.000 396.760 ;
        RECT 4.400 391.360 546.000 392.720 ;
        RECT 4.400 391.320 545.600 391.360 ;
        RECT 3.990 389.960 545.600 391.320 ;
        RECT 3.990 387.280 546.000 389.960 ;
        RECT 4.400 385.880 546.000 387.280 ;
        RECT 3.990 384.560 546.000 385.880 ;
        RECT 3.990 383.160 545.600 384.560 ;
        RECT 3.990 381.840 546.000 383.160 ;
        RECT 4.400 380.440 546.000 381.840 ;
        RECT 3.990 377.760 546.000 380.440 ;
        RECT 3.990 376.400 545.600 377.760 ;
        RECT 4.400 376.360 545.600 376.400 ;
        RECT 4.400 375.000 546.000 376.360 ;
        RECT 3.990 370.960 546.000 375.000 ;
        RECT 4.400 369.560 545.600 370.960 ;
        RECT 3.990 365.520 546.000 369.560 ;
        RECT 4.400 364.160 546.000 365.520 ;
        RECT 4.400 364.120 545.600 364.160 ;
        RECT 3.990 362.760 545.600 364.120 ;
        RECT 3.990 360.080 546.000 362.760 ;
        RECT 4.400 358.680 546.000 360.080 ;
        RECT 3.990 357.360 546.000 358.680 ;
        RECT 3.990 355.960 545.600 357.360 ;
        RECT 3.990 354.640 546.000 355.960 ;
        RECT 4.400 353.240 546.000 354.640 ;
        RECT 3.990 350.560 546.000 353.240 ;
        RECT 3.990 349.200 545.600 350.560 ;
        RECT 4.400 349.160 545.600 349.200 ;
        RECT 4.400 347.800 546.000 349.160 ;
        RECT 3.990 343.760 546.000 347.800 ;
        RECT 4.400 342.360 545.600 343.760 ;
        RECT 3.990 338.320 546.000 342.360 ;
        RECT 4.400 336.960 546.000 338.320 ;
        RECT 4.400 336.920 545.600 336.960 ;
        RECT 3.990 335.560 545.600 336.920 ;
        RECT 3.990 332.880 546.000 335.560 ;
        RECT 4.400 331.480 546.000 332.880 ;
        RECT 3.990 330.160 546.000 331.480 ;
        RECT 3.990 328.760 545.600 330.160 ;
        RECT 3.990 327.440 546.000 328.760 ;
        RECT 4.400 326.040 546.000 327.440 ;
        RECT 3.990 323.360 546.000 326.040 ;
        RECT 3.990 322.000 545.600 323.360 ;
        RECT 4.400 321.960 545.600 322.000 ;
        RECT 4.400 320.600 546.000 321.960 ;
        RECT 3.990 316.560 546.000 320.600 ;
        RECT 4.400 315.160 545.600 316.560 ;
        RECT 3.990 311.120 546.000 315.160 ;
        RECT 4.400 309.760 546.000 311.120 ;
        RECT 4.400 309.720 545.600 309.760 ;
        RECT 3.990 308.360 545.600 309.720 ;
        RECT 3.990 305.680 546.000 308.360 ;
        RECT 4.400 304.280 546.000 305.680 ;
        RECT 3.990 302.960 546.000 304.280 ;
        RECT 3.990 301.560 545.600 302.960 ;
        RECT 3.990 300.240 546.000 301.560 ;
        RECT 4.400 298.840 546.000 300.240 ;
        RECT 3.990 296.160 546.000 298.840 ;
        RECT 3.990 294.800 545.600 296.160 ;
        RECT 4.400 294.760 545.600 294.800 ;
        RECT 4.400 293.400 546.000 294.760 ;
        RECT 3.990 289.360 546.000 293.400 ;
        RECT 4.400 287.960 545.600 289.360 ;
        RECT 3.990 283.920 546.000 287.960 ;
        RECT 4.400 282.560 546.000 283.920 ;
        RECT 4.400 282.520 545.600 282.560 ;
        RECT 3.990 281.160 545.600 282.520 ;
        RECT 3.990 278.480 546.000 281.160 ;
        RECT 4.400 277.080 546.000 278.480 ;
        RECT 3.990 275.760 546.000 277.080 ;
        RECT 3.990 274.360 545.600 275.760 ;
        RECT 3.990 273.040 546.000 274.360 ;
        RECT 4.400 271.640 546.000 273.040 ;
        RECT 3.990 268.960 546.000 271.640 ;
        RECT 3.990 267.600 545.600 268.960 ;
        RECT 4.400 267.560 545.600 267.600 ;
        RECT 4.400 266.200 546.000 267.560 ;
        RECT 3.990 262.160 546.000 266.200 ;
        RECT 4.400 260.760 545.600 262.160 ;
        RECT 3.990 256.720 546.000 260.760 ;
        RECT 4.400 255.360 546.000 256.720 ;
        RECT 4.400 255.320 545.600 255.360 ;
        RECT 3.990 253.960 545.600 255.320 ;
        RECT 3.990 251.280 546.000 253.960 ;
        RECT 4.400 249.880 546.000 251.280 ;
        RECT 3.990 248.560 546.000 249.880 ;
        RECT 3.990 247.160 545.600 248.560 ;
        RECT 3.990 245.840 546.000 247.160 ;
        RECT 4.400 244.440 546.000 245.840 ;
        RECT 3.990 241.760 546.000 244.440 ;
        RECT 3.990 240.400 545.600 241.760 ;
        RECT 4.400 240.360 545.600 240.400 ;
        RECT 4.400 239.000 546.000 240.360 ;
        RECT 3.990 234.960 546.000 239.000 ;
        RECT 4.400 233.560 545.600 234.960 ;
        RECT 3.990 229.520 546.000 233.560 ;
        RECT 4.400 228.160 546.000 229.520 ;
        RECT 4.400 228.120 545.600 228.160 ;
        RECT 3.990 226.760 545.600 228.120 ;
        RECT 3.990 224.080 546.000 226.760 ;
        RECT 4.400 222.680 546.000 224.080 ;
        RECT 3.990 221.360 546.000 222.680 ;
        RECT 3.990 219.960 545.600 221.360 ;
        RECT 3.990 218.640 546.000 219.960 ;
        RECT 4.400 217.240 546.000 218.640 ;
        RECT 3.990 214.560 546.000 217.240 ;
        RECT 3.990 213.200 545.600 214.560 ;
        RECT 4.400 213.160 545.600 213.200 ;
        RECT 4.400 211.800 546.000 213.160 ;
        RECT 3.990 207.760 546.000 211.800 ;
        RECT 4.400 206.360 545.600 207.760 ;
        RECT 3.990 202.320 546.000 206.360 ;
        RECT 4.400 200.960 546.000 202.320 ;
        RECT 4.400 200.920 545.600 200.960 ;
        RECT 3.990 199.560 545.600 200.920 ;
        RECT 3.990 196.880 546.000 199.560 ;
        RECT 4.400 195.480 546.000 196.880 ;
        RECT 3.990 194.160 546.000 195.480 ;
        RECT 3.990 192.760 545.600 194.160 ;
        RECT 3.990 191.440 546.000 192.760 ;
        RECT 4.400 190.040 546.000 191.440 ;
        RECT 3.990 187.360 546.000 190.040 ;
        RECT 3.990 186.000 545.600 187.360 ;
        RECT 4.400 185.960 545.600 186.000 ;
        RECT 4.400 184.600 546.000 185.960 ;
        RECT 3.990 180.560 546.000 184.600 ;
        RECT 4.400 179.160 545.600 180.560 ;
        RECT 3.990 175.120 546.000 179.160 ;
        RECT 4.400 173.760 546.000 175.120 ;
        RECT 4.400 173.720 545.600 173.760 ;
        RECT 3.990 172.360 545.600 173.720 ;
        RECT 3.990 169.680 546.000 172.360 ;
        RECT 4.400 168.280 546.000 169.680 ;
        RECT 3.990 166.960 546.000 168.280 ;
        RECT 3.990 165.560 545.600 166.960 ;
        RECT 3.990 164.240 546.000 165.560 ;
        RECT 4.400 162.840 546.000 164.240 ;
        RECT 3.990 160.160 546.000 162.840 ;
        RECT 3.990 158.800 545.600 160.160 ;
        RECT 4.400 158.760 545.600 158.800 ;
        RECT 4.400 157.400 546.000 158.760 ;
        RECT 3.990 153.360 546.000 157.400 ;
        RECT 4.400 151.960 545.600 153.360 ;
        RECT 3.990 147.920 546.000 151.960 ;
        RECT 4.400 146.560 546.000 147.920 ;
        RECT 4.400 146.520 545.600 146.560 ;
        RECT 3.990 145.160 545.600 146.520 ;
        RECT 3.990 142.480 546.000 145.160 ;
        RECT 4.400 141.080 546.000 142.480 ;
        RECT 3.990 139.760 546.000 141.080 ;
        RECT 3.990 138.360 545.600 139.760 ;
        RECT 3.990 137.040 546.000 138.360 ;
        RECT 4.400 135.640 546.000 137.040 ;
        RECT 3.990 132.960 546.000 135.640 ;
        RECT 3.990 131.600 545.600 132.960 ;
        RECT 4.400 131.560 545.600 131.600 ;
        RECT 4.400 130.200 546.000 131.560 ;
        RECT 3.990 126.160 546.000 130.200 ;
        RECT 4.400 124.760 545.600 126.160 ;
        RECT 3.990 120.720 546.000 124.760 ;
        RECT 4.400 119.360 546.000 120.720 ;
        RECT 4.400 119.320 545.600 119.360 ;
        RECT 3.990 117.960 545.600 119.320 ;
        RECT 3.990 115.280 546.000 117.960 ;
        RECT 4.400 113.880 546.000 115.280 ;
        RECT 3.990 112.560 546.000 113.880 ;
        RECT 3.990 111.160 545.600 112.560 ;
        RECT 3.990 109.840 546.000 111.160 ;
        RECT 4.400 108.440 546.000 109.840 ;
        RECT 3.990 105.760 546.000 108.440 ;
        RECT 3.990 104.400 545.600 105.760 ;
        RECT 4.400 104.360 545.600 104.400 ;
        RECT 4.400 103.000 546.000 104.360 ;
        RECT 3.990 98.960 546.000 103.000 ;
        RECT 4.400 97.560 545.600 98.960 ;
        RECT 3.990 93.520 546.000 97.560 ;
        RECT 4.400 92.160 546.000 93.520 ;
        RECT 4.400 92.120 545.600 92.160 ;
        RECT 3.990 90.760 545.600 92.120 ;
        RECT 3.990 88.080 546.000 90.760 ;
        RECT 4.400 86.680 546.000 88.080 ;
        RECT 3.990 85.360 546.000 86.680 ;
        RECT 3.990 83.960 545.600 85.360 ;
        RECT 3.990 82.640 546.000 83.960 ;
        RECT 4.400 81.240 546.000 82.640 ;
        RECT 3.990 78.560 546.000 81.240 ;
        RECT 3.990 77.200 545.600 78.560 ;
        RECT 4.400 77.160 545.600 77.200 ;
        RECT 4.400 75.800 546.000 77.160 ;
        RECT 3.990 71.760 546.000 75.800 ;
        RECT 4.400 70.360 545.600 71.760 ;
        RECT 3.990 66.320 546.000 70.360 ;
        RECT 4.400 64.960 546.000 66.320 ;
        RECT 4.400 64.920 545.600 64.960 ;
        RECT 3.990 63.560 545.600 64.920 ;
        RECT 3.990 60.880 546.000 63.560 ;
        RECT 4.400 59.480 546.000 60.880 ;
        RECT 3.990 58.160 546.000 59.480 ;
        RECT 3.990 56.760 545.600 58.160 ;
        RECT 3.990 55.440 546.000 56.760 ;
        RECT 4.400 54.040 546.000 55.440 ;
        RECT 3.990 51.360 546.000 54.040 ;
        RECT 3.990 50.000 545.600 51.360 ;
        RECT 4.400 49.960 545.600 50.000 ;
        RECT 4.400 48.600 546.000 49.960 ;
        RECT 3.990 44.560 546.000 48.600 ;
        RECT 4.400 43.160 545.600 44.560 ;
        RECT 3.990 39.120 546.000 43.160 ;
        RECT 4.400 37.760 546.000 39.120 ;
        RECT 4.400 37.720 545.600 37.760 ;
        RECT 3.990 36.360 545.600 37.720 ;
        RECT 3.990 33.680 546.000 36.360 ;
        RECT 4.400 32.280 546.000 33.680 ;
        RECT 3.990 30.960 546.000 32.280 ;
        RECT 3.990 29.560 545.600 30.960 ;
        RECT 3.990 28.240 546.000 29.560 ;
        RECT 4.400 26.840 546.000 28.240 ;
        RECT 3.990 22.800 546.000 26.840 ;
        RECT 4.400 21.400 546.000 22.800 ;
        RECT 3.990 17.360 546.000 21.400 ;
        RECT 4.400 15.960 546.000 17.360 ;
        RECT 3.990 11.920 546.000 15.960 ;
        RECT 4.400 10.520 546.000 11.920 ;
        RECT 3.990 9.015 546.000 10.520 ;
      LAYER met4 ;
        RECT 37.095 12.415 174.240 534.985 ;
        RECT 176.640 12.415 177.540 534.985 ;
        RECT 179.940 12.415 327.840 534.985 ;
        RECT 330.240 12.415 331.140 534.985 ;
        RECT 333.540 12.415 481.440 534.985 ;
        RECT 483.840 12.415 484.740 534.985 ;
        RECT 487.140 12.415 514.905 534.985 ;
  END
END core_m
END LIBRARY

